VERSION 5.7 ;
  NOWIREEXTENSIONATPIN ON ;
  DIVIDERCHAR "/" ;
  BUSBITCHARS "[]" ;
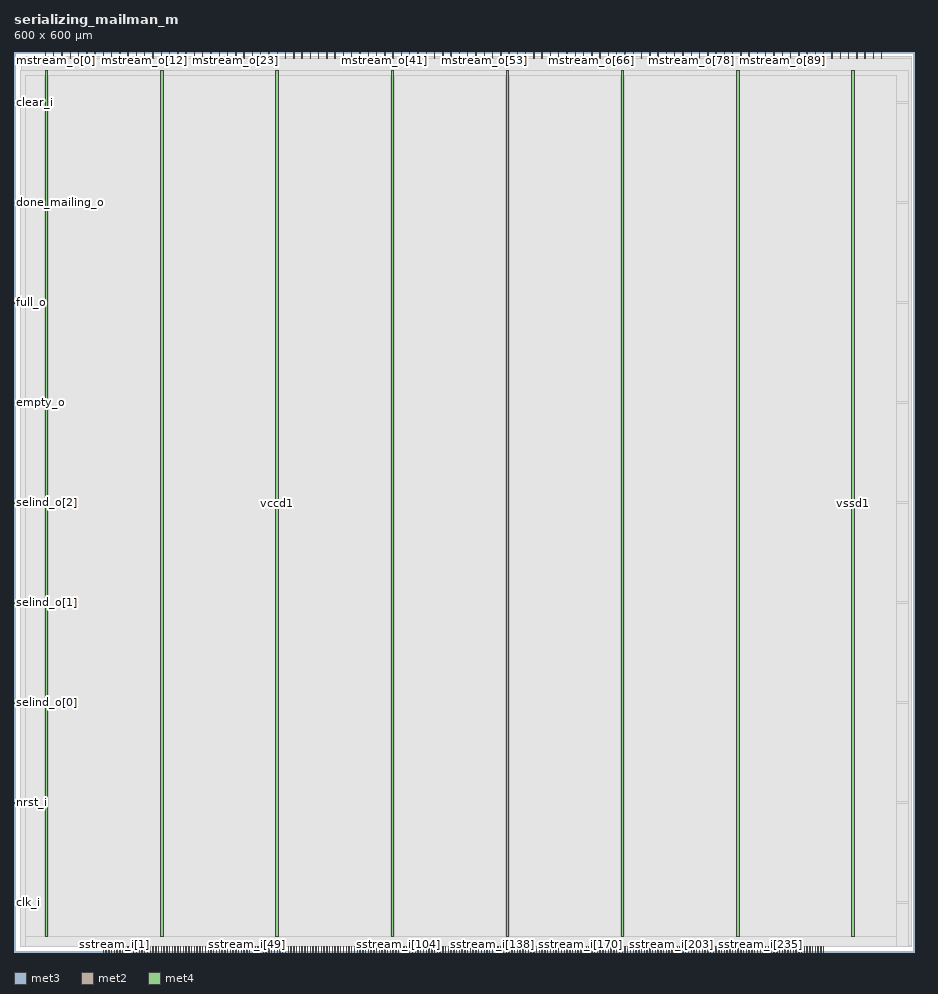
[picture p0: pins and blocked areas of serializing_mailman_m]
MACRO serializing_mailman_m
  CLASS BLOCK ;
  FOREIGN serializing_mailman_m ;
  ORIGIN 0.000 0.000 ;
  SIZE 600.000 BY 600.000 ;
  PIN clear_i
    DIRECTION INPUT ;
    USE SIGNAL ;
    ANTENNAGATEAREA 0.159000 ;
    PORT
      LAYER met3 ;
        RECT 0.000 565.800 4.000 566.400 ;
    END
  END clear_i
  PIN clk_i
    DIRECTION INPUT ;
    USE SIGNAL ;
    ANTENNAGATEAREA 0.852000 ;
    ANTENNADIFFAREA 0.434700 ;
    PORT
      LAYER met3 ;
        RECT 0.000 32.680 4.000 33.280 ;
    END
  END clk_i
  PIN done_mailing_o
    DIRECTION OUTPUT TRISTATE ;
    USE SIGNAL ;
    ANTENNADIFFAREA 0.795200 ;
    PORT
      LAYER met3 ;
        RECT 0.000 499.160 4.000 499.760 ;
    END
  END done_mailing_o
  PIN empty_o
    DIRECTION OUTPUT TRISTATE ;
    USE SIGNAL ;
    ANTENNADIFFAREA 0.795200 ;
    PORT
      LAYER met3 ;
        RECT 0.000 365.880 4.000 366.480 ;
    END
  END empty_o
  PIN full_o
    DIRECTION OUTPUT TRISTATE ;
    USE SIGNAL ;
    ANTENNADIFFAREA 0.795200 ;
    PORT
      LAYER met3 ;
        RECT 0.000 432.520 4.000 433.120 ;
    END
  END full_o
  PIN mstream_i[0]
    DIRECTION INPUT ;
    USE SIGNAL ;
    ANTENNAGATEAREA 0.213000 ;
    PORT
      LAYER met2 ;
        RECT 59.430 0.000 59.710 4.000 ;
    END
  END mstream_i[0]
  PIN mstream_i[1]
    DIRECTION INPUT ;
    USE SIGNAL ;
    ANTENNAGATEAREA 0.213000 ;
    PORT
      LAYER met2 ;
        RECT 61.270 0.000 61.550 4.000 ;
    END
  END mstream_i[1]
  PIN mstream_i[2]
    DIRECTION INPUT ;
    USE SIGNAL ;
    ANTENNAGATEAREA 0.213000 ;
    PORT
      LAYER met2 ;
        RECT 63.110 0.000 63.390 4.000 ;
    END
  END mstream_i[2]
  PIN mstream_o[0]
    DIRECTION OUTPUT TRISTATE ;
    USE SIGNAL ;
    ANTENNADIFFAREA 0.795200 ;
    PORT
      LAYER met2 ;
        RECT 20.790 596.000 21.070 600.000 ;
    END
  END mstream_o[0]
  PIN mstream_o[100]
    DIRECTION OUTPUT TRISTATE ;
    USE SIGNAL ;
    ANTENNADIFFAREA 0.795200 ;
    PORT
      LAYER met2 ;
        RECT 572.790 596.000 573.070 600.000 ;
    END
  END mstream_o[100]
  PIN mstream_o[101]
    DIRECTION OUTPUT TRISTATE ;
    USE SIGNAL ;
    PORT
      LAYER met2 ;
        RECT 578.310 596.000 578.590 600.000 ;
    END
  END mstream_o[101]
  PIN mstream_o[10]
    DIRECTION OUTPUT TRISTATE ;
    USE SIGNAL ;
    ANTENNADIFFAREA 0.795200 ;
    PORT
      LAYER met2 ;
        RECT 75.990 596.000 76.270 600.000 ;
    END
  END mstream_o[10]
  PIN mstream_o[11]
    DIRECTION OUTPUT TRISTATE ;
    USE SIGNAL ;
    ANTENNADIFFAREA 0.795200 ;
    PORT
      LAYER met2 ;
        RECT 81.510 596.000 81.790 600.000 ;
    END
  END mstream_o[11]
  PIN mstream_o[12]
    DIRECTION OUTPUT TRISTATE ;
    USE SIGNAL ;
    ANTENNADIFFAREA 0.795200 ;
    PORT
      LAYER met2 ;
        RECT 87.030 596.000 87.310 600.000 ;
    END
  END mstream_o[12]
  PIN mstream_o[13]
    DIRECTION OUTPUT TRISTATE ;
    USE SIGNAL ;
    ANTENNADIFFAREA 0.795200 ;
    PORT
      LAYER met2 ;
        RECT 92.550 596.000 92.830 600.000 ;
    END
  END mstream_o[13]
  PIN mstream_o[14]
    DIRECTION OUTPUT TRISTATE ;
    USE SIGNAL ;
    ANTENNADIFFAREA 0.795200 ;
    PORT
      LAYER met2 ;
        RECT 98.070 596.000 98.350 600.000 ;
    END
  END mstream_o[14]
  PIN mstream_o[15]
    DIRECTION OUTPUT TRISTATE ;
    USE SIGNAL ;
    ANTENNADIFFAREA 0.795200 ;
    PORT
      LAYER met2 ;
        RECT 103.590 596.000 103.870 600.000 ;
    END
  END mstream_o[15]
  PIN mstream_o[16]
    DIRECTION OUTPUT TRISTATE ;
    USE SIGNAL ;
    ANTENNADIFFAREA 0.795200 ;
    PORT
      LAYER met2 ;
        RECT 109.110 596.000 109.390 600.000 ;
    END
  END mstream_o[16]
  PIN mstream_o[17]
    DIRECTION OUTPUT TRISTATE ;
    USE SIGNAL ;
    ANTENNADIFFAREA 0.795200 ;
    PORT
      LAYER met2 ;
        RECT 114.630 596.000 114.910 600.000 ;
    END
  END mstream_o[17]
  PIN mstream_o[18]
    DIRECTION OUTPUT TRISTATE ;
    USE SIGNAL ;
    ANTENNADIFFAREA 0.795200 ;
    PORT
      LAYER met2 ;
        RECT 120.150 596.000 120.430 600.000 ;
    END
  END mstream_o[18]
  PIN mstream_o[19]
    DIRECTION OUTPUT TRISTATE ;
    USE SIGNAL ;
    ANTENNADIFFAREA 0.795200 ;
    PORT
      LAYER met2 ;
        RECT 125.670 596.000 125.950 600.000 ;
    END
  END mstream_o[19]
  PIN mstream_o[1]
    DIRECTION OUTPUT TRISTATE ;
    USE SIGNAL ;
    ANTENNADIFFAREA 0.795200 ;
    PORT
      LAYER met2 ;
        RECT 26.310 596.000 26.590 600.000 ;
    END
  END mstream_o[1]
  PIN mstream_o[20]
    DIRECTION OUTPUT TRISTATE ;
    USE SIGNAL ;
    ANTENNADIFFAREA 0.795200 ;
    PORT
      LAYER met2 ;
        RECT 131.190 596.000 131.470 600.000 ;
    END
  END mstream_o[20]
  PIN mstream_o[21]
    DIRECTION OUTPUT TRISTATE ;
    USE SIGNAL ;
    ANTENNADIFFAREA 0.795200 ;
    PORT
      LAYER met2 ;
        RECT 136.710 596.000 136.990 600.000 ;
    END
  END mstream_o[21]
  PIN mstream_o[22]
    DIRECTION OUTPUT TRISTATE ;
    USE SIGNAL ;
    ANTENNADIFFAREA 0.795200 ;
    PORT
      LAYER met2 ;
        RECT 142.230 596.000 142.510 600.000 ;
    END
  END mstream_o[22]
  PIN mstream_o[23]
    DIRECTION OUTPUT TRISTATE ;
    USE SIGNAL ;
    ANTENNADIFFAREA 0.795200 ;
    PORT
      LAYER met2 ;
        RECT 147.750 596.000 148.030 600.000 ;
    END
  END mstream_o[23]
  PIN mstream_o[24]
    DIRECTION OUTPUT TRISTATE ;
    USE SIGNAL ;
    ANTENNADIFFAREA 0.795200 ;
    PORT
      LAYER met2 ;
        RECT 153.270 596.000 153.550 600.000 ;
    END
  END mstream_o[24]
  PIN mstream_o[25]
    DIRECTION OUTPUT TRISTATE ;
    USE SIGNAL ;
    ANTENNADIFFAREA 0.795200 ;
    PORT
      LAYER met2 ;
        RECT 158.790 596.000 159.070 600.000 ;
    END
  END mstream_o[25]
  PIN mstream_o[26]
    DIRECTION OUTPUT TRISTATE ;
    USE SIGNAL ;
    ANTENNADIFFAREA 0.795200 ;
    PORT
      LAYER met2 ;
        RECT 164.310 596.000 164.590 600.000 ;
    END
  END mstream_o[26]
  PIN mstream_o[27]
    DIRECTION OUTPUT TRISTATE ;
    USE SIGNAL ;
    ANTENNADIFFAREA 0.795200 ;
    PORT
      LAYER met2 ;
        RECT 169.830 596.000 170.110 600.000 ;
    END
  END mstream_o[27]
  PIN mstream_o[28]
    DIRECTION OUTPUT TRISTATE ;
    USE SIGNAL ;
    ANTENNADIFFAREA 0.795200 ;
    PORT
      LAYER met2 ;
        RECT 175.350 596.000 175.630 600.000 ;
    END
  END mstream_o[28]
  PIN mstream_o[29]
    DIRECTION OUTPUT TRISTATE ;
    USE SIGNAL ;
    ANTENNADIFFAREA 0.795200 ;
    PORT
      LAYER met2 ;
        RECT 180.870 596.000 181.150 600.000 ;
    END
  END mstream_o[29]
  PIN mstream_o[2]
    DIRECTION OUTPUT TRISTATE ;
    USE SIGNAL ;
    ANTENNADIFFAREA 0.795200 ;
    PORT
      LAYER met2 ;
        RECT 31.830 596.000 32.110 600.000 ;
    END
  END mstream_o[2]
  PIN mstream_o[30]
    DIRECTION OUTPUT TRISTATE ;
    USE SIGNAL ;
    ANTENNADIFFAREA 0.795200 ;
    PORT
      LAYER met2 ;
        RECT 186.390 596.000 186.670 600.000 ;
    END
  END mstream_o[30]
  PIN mstream_o[31]
    DIRECTION OUTPUT TRISTATE ;
    USE SIGNAL ;
    ANTENNADIFFAREA 0.795200 ;
    PORT
      LAYER met2 ;
        RECT 191.910 596.000 192.190 600.000 ;
    END
  END mstream_o[31]
  PIN mstream_o[32]
    DIRECTION OUTPUT TRISTATE ;
    USE SIGNAL ;
    ANTENNADIFFAREA 0.795200 ;
    PORT
      LAYER met2 ;
        RECT 197.430 596.000 197.710 600.000 ;
    END
  END mstream_o[32]
  PIN mstream_o[33]
    DIRECTION OUTPUT TRISTATE ;
    USE SIGNAL ;
    PORT
      LAYER met2 ;
        RECT 202.950 596.000 203.230 600.000 ;
    END
  END mstream_o[33]
  PIN mstream_o[34]
    DIRECTION OUTPUT TRISTATE ;
    USE SIGNAL ;
    ANTENNADIFFAREA 0.795200 ;
    PORT
      LAYER met2 ;
        RECT 208.470 596.000 208.750 600.000 ;
    END
  END mstream_o[34]
  PIN mstream_o[35]
    DIRECTION OUTPUT TRISTATE ;
    USE SIGNAL ;
    ANTENNADIFFAREA 0.795200 ;
    PORT
      LAYER met2 ;
        RECT 213.990 596.000 214.270 600.000 ;
    END
  END mstream_o[35]
  PIN mstream_o[36]
    DIRECTION OUTPUT TRISTATE ;
    USE SIGNAL ;
    ANTENNADIFFAREA 0.795200 ;
    PORT
      LAYER met2 ;
        RECT 219.510 596.000 219.790 600.000 ;
    END
  END mstream_o[36]
  PIN mstream_o[37]
    DIRECTION OUTPUT TRISTATE ;
    USE SIGNAL ;
    ANTENNADIFFAREA 0.795200 ;
    PORT
      LAYER met2 ;
        RECT 225.030 596.000 225.310 600.000 ;
    END
  END mstream_o[37]
  PIN mstream_o[38]
    DIRECTION OUTPUT TRISTATE ;
    USE SIGNAL ;
    ANTENNADIFFAREA 0.795200 ;
    PORT
      LAYER met2 ;
        RECT 230.550 596.000 230.830 600.000 ;
    END
  END mstream_o[38]
  PIN mstream_o[39]
    DIRECTION OUTPUT TRISTATE ;
    USE SIGNAL ;
    ANTENNADIFFAREA 0.795200 ;
    PORT
      LAYER met2 ;
        RECT 236.070 596.000 236.350 600.000 ;
    END
  END mstream_o[39]
  PIN mstream_o[3]
    DIRECTION OUTPUT TRISTATE ;
    USE SIGNAL ;
    ANTENNADIFFAREA 0.795200 ;
    PORT
      LAYER met2 ;
        RECT 37.350 596.000 37.630 600.000 ;
    END
  END mstream_o[3]
  PIN mstream_o[40]
    DIRECTION OUTPUT TRISTATE ;
    USE SIGNAL ;
    ANTENNADIFFAREA 0.795200 ;
    PORT
      LAYER met2 ;
        RECT 241.590 596.000 241.870 600.000 ;
    END
  END mstream_o[40]
  PIN mstream_o[41]
    DIRECTION OUTPUT TRISTATE ;
    USE SIGNAL ;
    ANTENNADIFFAREA 0.795200 ;
    PORT
      LAYER met2 ;
        RECT 247.110 596.000 247.390 600.000 ;
    END
  END mstream_o[41]
  PIN mstream_o[42]
    DIRECTION OUTPUT TRISTATE ;
    USE SIGNAL ;
    ANTENNADIFFAREA 0.795200 ;
    PORT
      LAYER met2 ;
        RECT 252.630 596.000 252.910 600.000 ;
    END
  END mstream_o[42]
  PIN mstream_o[43]
    DIRECTION OUTPUT TRISTATE ;
    USE SIGNAL ;
    ANTENNADIFFAREA 0.795200 ;
    PORT
      LAYER met2 ;
        RECT 258.150 596.000 258.430 600.000 ;
    END
  END mstream_o[43]
  PIN mstream_o[44]
    DIRECTION OUTPUT TRISTATE ;
    USE SIGNAL ;
    ANTENNADIFFAREA 0.795200 ;
    PORT
      LAYER met2 ;
        RECT 263.670 596.000 263.950 600.000 ;
    END
  END mstream_o[44]
  PIN mstream_o[45]
    DIRECTION OUTPUT TRISTATE ;
    USE SIGNAL ;
    ANTENNADIFFAREA 0.795200 ;
    PORT
      LAYER met2 ;
        RECT 269.190 596.000 269.470 600.000 ;
    END
  END mstream_o[45]
  PIN mstream_o[46]
    DIRECTION OUTPUT TRISTATE ;
    USE SIGNAL ;
    ANTENNADIFFAREA 0.795200 ;
    PORT
      LAYER met2 ;
        RECT 274.710 596.000 274.990 600.000 ;
    END
  END mstream_o[46]
  PIN mstream_o[47]
    DIRECTION OUTPUT TRISTATE ;
    USE SIGNAL ;
    ANTENNADIFFAREA 0.795200 ;
    PORT
      LAYER met2 ;
        RECT 280.230 596.000 280.510 600.000 ;
    END
  END mstream_o[47]
  PIN mstream_o[48]
    DIRECTION OUTPUT TRISTATE ;
    USE SIGNAL ;
    ANTENNADIFFAREA 0.795200 ;
    PORT
      LAYER met2 ;
        RECT 285.750 596.000 286.030 600.000 ;
    END
  END mstream_o[48]
  PIN mstream_o[49]
    DIRECTION OUTPUT TRISTATE ;
    USE SIGNAL ;
    ANTENNADIFFAREA 0.795200 ;
    PORT
      LAYER met2 ;
        RECT 291.270 596.000 291.550 600.000 ;
    END
  END mstream_o[49]
  PIN mstream_o[4]
    DIRECTION OUTPUT TRISTATE ;
    USE SIGNAL ;
    ANTENNADIFFAREA 0.795200 ;
    PORT
      LAYER met2 ;
        RECT 42.870 596.000 43.150 600.000 ;
    END
  END mstream_o[4]
  PIN mstream_o[50]
    DIRECTION OUTPUT TRISTATE ;
    USE SIGNAL ;
    ANTENNADIFFAREA 0.795200 ;
    PORT
      LAYER met2 ;
        RECT 296.790 596.000 297.070 600.000 ;
    END
  END mstream_o[50]
  PIN mstream_o[51]
    DIRECTION OUTPUT TRISTATE ;
    USE SIGNAL ;
    ANTENNADIFFAREA 0.795200 ;
    PORT
      LAYER met2 ;
        RECT 302.310 596.000 302.590 600.000 ;
    END
  END mstream_o[51]
  PIN mstream_o[52]
    DIRECTION OUTPUT TRISTATE ;
    USE SIGNAL ;
    ANTENNADIFFAREA 0.795200 ;
    PORT
      LAYER met2 ;
        RECT 307.830 596.000 308.110 600.000 ;
    END
  END mstream_o[52]
  PIN mstream_o[53]
    DIRECTION OUTPUT TRISTATE ;
    USE SIGNAL ;
    ANTENNADIFFAREA 0.795200 ;
    PORT
      LAYER met2 ;
        RECT 313.350 596.000 313.630 600.000 ;
    END
  END mstream_o[53]
  PIN mstream_o[54]
    DIRECTION OUTPUT TRISTATE ;
    USE SIGNAL ;
    ANTENNADIFFAREA 0.795200 ;
    PORT
      LAYER met2 ;
        RECT 318.870 596.000 319.150 600.000 ;
    END
  END mstream_o[54]
  PIN mstream_o[55]
    DIRECTION OUTPUT TRISTATE ;
    USE SIGNAL ;
    ANTENNADIFFAREA 0.795200 ;
    PORT
      LAYER met2 ;
        RECT 324.390 596.000 324.670 600.000 ;
    END
  END mstream_o[55]
  PIN mstream_o[56]
    DIRECTION OUTPUT TRISTATE ;
    USE SIGNAL ;
    ANTENNADIFFAREA 0.795200 ;
    PORT
      LAYER met2 ;
        RECT 329.910 596.000 330.190 600.000 ;
    END
  END mstream_o[56]
  PIN mstream_o[57]
    DIRECTION OUTPUT TRISTATE ;
    USE SIGNAL ;
    ANTENNADIFFAREA 0.795200 ;
    PORT
      LAYER met2 ;
        RECT 335.430 596.000 335.710 600.000 ;
    END
  END mstream_o[57]
  PIN mstream_o[58]
    DIRECTION OUTPUT TRISTATE ;
    USE SIGNAL ;
    ANTENNADIFFAREA 0.795200 ;
    PORT
      LAYER met2 ;
        RECT 340.950 596.000 341.230 600.000 ;
    END
  END mstream_o[58]
  PIN mstream_o[59]
    DIRECTION OUTPUT TRISTATE ;
    USE SIGNAL ;
    ANTENNADIFFAREA 0.795200 ;
    PORT
      LAYER met2 ;
        RECT 346.470 596.000 346.750 600.000 ;
    END
  END mstream_o[59]
  PIN mstream_o[5]
    DIRECTION OUTPUT TRISTATE ;
    USE SIGNAL ;
    ANTENNADIFFAREA 0.795200 ;
    PORT
      LAYER met2 ;
        RECT 48.390 596.000 48.670 600.000 ;
    END
  END mstream_o[5]
  PIN mstream_o[60]
    DIRECTION OUTPUT TRISTATE ;
    USE SIGNAL ;
    ANTENNADIFFAREA 0.795200 ;
    PORT
      LAYER met2 ;
        RECT 351.990 596.000 352.270 600.000 ;
    END
  END mstream_o[60]
  PIN mstream_o[61]
    DIRECTION OUTPUT TRISTATE ;
    USE SIGNAL ;
    ANTENNADIFFAREA 0.795200 ;
    PORT
      LAYER met2 ;
        RECT 357.510 596.000 357.790 600.000 ;
    END
  END mstream_o[61]
  PIN mstream_o[62]
    DIRECTION OUTPUT TRISTATE ;
    USE SIGNAL ;
    ANTENNADIFFAREA 0.795200 ;
    PORT
      LAYER met2 ;
        RECT 363.030 596.000 363.310 600.000 ;
    END
  END mstream_o[62]
  PIN mstream_o[63]
    DIRECTION OUTPUT TRISTATE ;
    USE SIGNAL ;
    ANTENNADIFFAREA 0.795200 ;
    PORT
      LAYER met2 ;
        RECT 368.550 596.000 368.830 600.000 ;
    END
  END mstream_o[63]
  PIN mstream_o[64]
    DIRECTION OUTPUT TRISTATE ;
    USE SIGNAL ;
    ANTENNADIFFAREA 0.795200 ;
    PORT
      LAYER met2 ;
        RECT 374.070 596.000 374.350 600.000 ;
    END
  END mstream_o[64]
  PIN mstream_o[65]
    DIRECTION OUTPUT TRISTATE ;
    USE SIGNAL ;
    ANTENNADIFFAREA 0.795200 ;
    PORT
      LAYER met2 ;
        RECT 379.590 596.000 379.870 600.000 ;
    END
  END mstream_o[65]
  PIN mstream_o[66]
    DIRECTION OUTPUT TRISTATE ;
    USE SIGNAL ;
    ANTENNADIFFAREA 0.795200 ;
    PORT
      LAYER met2 ;
        RECT 385.110 596.000 385.390 600.000 ;
    END
  END mstream_o[66]
  PIN mstream_o[67]
    DIRECTION OUTPUT TRISTATE ;
    USE SIGNAL ;
    PORT
      LAYER met2 ;
        RECT 390.630 596.000 390.910 600.000 ;
    END
  END mstream_o[67]
  PIN mstream_o[68]
    DIRECTION OUTPUT TRISTATE ;
    USE SIGNAL ;
    ANTENNADIFFAREA 0.795200 ;
    PORT
      LAYER met2 ;
        RECT 396.150 596.000 396.430 600.000 ;
    END
  END mstream_o[68]
  PIN mstream_o[69]
    DIRECTION OUTPUT TRISTATE ;
    USE SIGNAL ;
    ANTENNADIFFAREA 0.795200 ;
    PORT
      LAYER met2 ;
        RECT 401.670 596.000 401.950 600.000 ;
    END
  END mstream_o[69]
  PIN mstream_o[6]
    DIRECTION OUTPUT TRISTATE ;
    USE SIGNAL ;
    ANTENNADIFFAREA 0.795200 ;
    PORT
      LAYER met2 ;
        RECT 53.910 596.000 54.190 600.000 ;
    END
  END mstream_o[6]
  PIN mstream_o[70]
    DIRECTION OUTPUT TRISTATE ;
    USE SIGNAL ;
    ANTENNADIFFAREA 0.795200 ;
    PORT
      LAYER met2 ;
        RECT 407.190 596.000 407.470 600.000 ;
    END
  END mstream_o[70]
  PIN mstream_o[71]
    DIRECTION OUTPUT TRISTATE ;
    USE SIGNAL ;
    ANTENNADIFFAREA 0.795200 ;
    PORT
      LAYER met2 ;
        RECT 412.710 596.000 412.990 600.000 ;
    END
  END mstream_o[71]
  PIN mstream_o[72]
    DIRECTION OUTPUT TRISTATE ;
    USE SIGNAL ;
    ANTENNADIFFAREA 0.795200 ;
    PORT
      LAYER met2 ;
        RECT 418.230 596.000 418.510 600.000 ;
    END
  END mstream_o[72]
  PIN mstream_o[73]
    DIRECTION OUTPUT TRISTATE ;
    USE SIGNAL ;
    ANTENNADIFFAREA 0.795200 ;
    PORT
      LAYER met2 ;
        RECT 423.750 596.000 424.030 600.000 ;
    END
  END mstream_o[73]
  PIN mstream_o[74]
    DIRECTION OUTPUT TRISTATE ;
    USE SIGNAL ;
    ANTENNADIFFAREA 0.795200 ;
    PORT
      LAYER met2 ;
        RECT 429.270 596.000 429.550 600.000 ;
    END
  END mstream_o[74]
  PIN mstream_o[75]
    DIRECTION OUTPUT TRISTATE ;
    USE SIGNAL ;
    ANTENNADIFFAREA 0.795200 ;
    PORT
      LAYER met2 ;
        RECT 434.790 596.000 435.070 600.000 ;
    END
  END mstream_o[75]
  PIN mstream_o[76]
    DIRECTION OUTPUT TRISTATE ;
    USE SIGNAL ;
    ANTENNADIFFAREA 0.795200 ;
    PORT
      LAYER met2 ;
        RECT 440.310 596.000 440.590 600.000 ;
    END
  END mstream_o[76]
  PIN mstream_o[77]
    DIRECTION OUTPUT TRISTATE ;
    USE SIGNAL ;
    ANTENNADIFFAREA 0.795200 ;
    PORT
      LAYER met2 ;
        RECT 445.830 596.000 446.110 600.000 ;
    END
  END mstream_o[77]
  PIN mstream_o[78]
    DIRECTION OUTPUT TRISTATE ;
    USE SIGNAL ;
    ANTENNADIFFAREA 0.795200 ;
    PORT
      LAYER met2 ;
        RECT 451.350 596.000 451.630 600.000 ;
    END
  END mstream_o[78]
  PIN mstream_o[79]
    DIRECTION OUTPUT TRISTATE ;
    USE SIGNAL ;
    ANTENNADIFFAREA 0.795200 ;
    PORT
      LAYER met2 ;
        RECT 456.870 596.000 457.150 600.000 ;
    END
  END mstream_o[79]
  PIN mstream_o[7]
    DIRECTION OUTPUT TRISTATE ;
    USE SIGNAL ;
    ANTENNADIFFAREA 0.795200 ;
    PORT
      LAYER met2 ;
        RECT 59.430 596.000 59.710 600.000 ;
    END
  END mstream_o[7]
  PIN mstream_o[80]
    DIRECTION OUTPUT TRISTATE ;
    USE SIGNAL ;
    ANTENNADIFFAREA 0.795200 ;
    PORT
      LAYER met2 ;
        RECT 462.390 596.000 462.670 600.000 ;
    END
  END mstream_o[80]
  PIN mstream_o[81]
    DIRECTION OUTPUT TRISTATE ;
    USE SIGNAL ;
    ANTENNADIFFAREA 0.795200 ;
    PORT
      LAYER met2 ;
        RECT 467.910 596.000 468.190 600.000 ;
    END
  END mstream_o[81]
  PIN mstream_o[82]
    DIRECTION OUTPUT TRISTATE ;
    USE SIGNAL ;
    ANTENNADIFFAREA 0.795200 ;
    PORT
      LAYER met2 ;
        RECT 473.430 596.000 473.710 600.000 ;
    END
  END mstream_o[82]
  PIN mstream_o[83]
    DIRECTION OUTPUT TRISTATE ;
    USE SIGNAL ;
    ANTENNADIFFAREA 0.795200 ;
    PORT
      LAYER met2 ;
        RECT 478.950 596.000 479.230 600.000 ;
    END
  END mstream_o[83]
  PIN mstream_o[84]
    DIRECTION OUTPUT TRISTATE ;
    USE SIGNAL ;
    ANTENNADIFFAREA 0.795200 ;
    PORT
      LAYER met2 ;
        RECT 484.470 596.000 484.750 600.000 ;
    END
  END mstream_o[84]
  PIN mstream_o[85]
    DIRECTION OUTPUT TRISTATE ;
    USE SIGNAL ;
    ANTENNADIFFAREA 0.795200 ;
    PORT
      LAYER met2 ;
        RECT 489.990 596.000 490.270 600.000 ;
    END
  END mstream_o[85]
  PIN mstream_o[86]
    DIRECTION OUTPUT TRISTATE ;
    USE SIGNAL ;
    ANTENNADIFFAREA 0.795200 ;
    PORT
      LAYER met2 ;
        RECT 495.510 596.000 495.790 600.000 ;
    END
  END mstream_o[86]
  PIN mstream_o[87]
    DIRECTION OUTPUT TRISTATE ;
    USE SIGNAL ;
    ANTENNADIFFAREA 0.795200 ;
    PORT
      LAYER met2 ;
        RECT 501.030 596.000 501.310 600.000 ;
    END
  END mstream_o[87]
  PIN mstream_o[88]
    DIRECTION OUTPUT TRISTATE ;
    USE SIGNAL ;
    ANTENNADIFFAREA 0.795200 ;
    PORT
      LAYER met2 ;
        RECT 506.550 596.000 506.830 600.000 ;
    END
  END mstream_o[88]
  PIN mstream_o[89]
    DIRECTION OUTPUT TRISTATE ;
    USE SIGNAL ;
    ANTENNADIFFAREA 0.795200 ;
    PORT
      LAYER met2 ;
        RECT 512.070 596.000 512.350 600.000 ;
    END
  END mstream_o[89]
  PIN mstream_o[8]
    DIRECTION OUTPUT TRISTATE ;
    USE SIGNAL ;
    ANTENNADIFFAREA 0.795200 ;
    PORT
      LAYER met2 ;
        RECT 64.950 596.000 65.230 600.000 ;
    END
  END mstream_o[8]
  PIN mstream_o[90]
    DIRECTION OUTPUT TRISTATE ;
    USE SIGNAL ;
    ANTENNADIFFAREA 0.795200 ;
    PORT
      LAYER met2 ;
        RECT 517.590 596.000 517.870 600.000 ;
    END
  END mstream_o[90]
  PIN mstream_o[91]
    DIRECTION OUTPUT TRISTATE ;
    USE SIGNAL ;
    ANTENNADIFFAREA 0.795200 ;
    PORT
      LAYER met2 ;
        RECT 523.110 596.000 523.390 600.000 ;
    END
  END mstream_o[91]
  PIN mstream_o[92]
    DIRECTION OUTPUT TRISTATE ;
    USE SIGNAL ;
    ANTENNADIFFAREA 0.795200 ;
    PORT
      LAYER met2 ;
        RECT 528.630 596.000 528.910 600.000 ;
    END
  END mstream_o[92]
  PIN mstream_o[93]
    DIRECTION OUTPUT TRISTATE ;
    USE SIGNAL ;
    ANTENNADIFFAREA 0.795200 ;
    PORT
      LAYER met2 ;
        RECT 534.150 596.000 534.430 600.000 ;
    END
  END mstream_o[93]
  PIN mstream_o[94]
    DIRECTION OUTPUT TRISTATE ;
    USE SIGNAL ;
    ANTENNADIFFAREA 0.795200 ;
    PORT
      LAYER met2 ;
        RECT 539.670 596.000 539.950 600.000 ;
    END
  END mstream_o[94]
  PIN mstream_o[95]
    DIRECTION OUTPUT TRISTATE ;
    USE SIGNAL ;
    ANTENNADIFFAREA 0.795200 ;
    PORT
      LAYER met2 ;
        RECT 545.190 596.000 545.470 600.000 ;
    END
  END mstream_o[95]
  PIN mstream_o[96]
    DIRECTION OUTPUT TRISTATE ;
    USE SIGNAL ;
    ANTENNADIFFAREA 0.795200 ;
    PORT
      LAYER met2 ;
        RECT 550.710 596.000 550.990 600.000 ;
    END
  END mstream_o[96]
  PIN mstream_o[97]
    DIRECTION OUTPUT TRISTATE ;
    USE SIGNAL ;
    ANTENNADIFFAREA 0.795200 ;
    PORT
      LAYER met2 ;
        RECT 556.230 596.000 556.510 600.000 ;
    END
  END mstream_o[97]
  PIN mstream_o[98]
    DIRECTION OUTPUT TRISTATE ;
    USE SIGNAL ;
    ANTENNADIFFAREA 0.795200 ;
    PORT
      LAYER met2 ;
        RECT 561.750 596.000 562.030 600.000 ;
    END
  END mstream_o[98]
  PIN mstream_o[99]
    DIRECTION OUTPUT TRISTATE ;
    USE SIGNAL ;
    ANTENNADIFFAREA 0.795200 ;
    PORT
      LAYER met2 ;
        RECT 567.270 596.000 567.550 600.000 ;
    END
  END mstream_o[99]
  PIN mstream_o[9]
    DIRECTION OUTPUT TRISTATE ;
    USE SIGNAL ;
    ANTENNADIFFAREA 0.795200 ;
    PORT
      LAYER met2 ;
        RECT 70.470 596.000 70.750 600.000 ;
    END
  END mstream_o[9]
  PIN nrst_i
    DIRECTION INPUT ;
    USE SIGNAL ;
    ANTENNAGATEAREA 0.196500 ;
    PORT
      LAYER met3 ;
        RECT 0.000 99.320 4.000 99.920 ;
    END
  END nrst_i
  PIN selind_o[0]
    DIRECTION OUTPUT TRISTATE ;
    USE SIGNAL ;
    ANTENNADIFFAREA 0.795200 ;
    PORT
      LAYER met3 ;
        RECT 0.000 165.960 4.000 166.560 ;
    END
  END selind_o[0]
  PIN selind_o[1]
    DIRECTION OUTPUT TRISTATE ;
    USE SIGNAL ;
    ANTENNADIFFAREA 0.795200 ;
    PORT
      LAYER met3 ;
        RECT 0.000 232.600 4.000 233.200 ;
    END
  END selind_o[1]
  PIN selind_o[2]
    DIRECTION OUTPUT TRISTATE ;
    USE SIGNAL ;
    ANTENNADIFFAREA 0.795200 ;
    PORT
      LAYER met3 ;
        RECT 0.000 299.240 4.000 299.840 ;
    END
  END selind_o[2]
  PIN sstream_i[0]
    DIRECTION INPUT ;
    USE SIGNAL ;
    ANTENNAGATEAREA 0.196500 ;
    PORT
      LAYER met2 ;
        RECT 64.950 0.000 65.230 4.000 ;
    END
  END sstream_i[0]
  PIN sstream_i[100]
    DIRECTION INPUT ;
    USE SIGNAL ;
    ANTENNAGATEAREA 0.159000 ;
    PORT
      LAYER met2 ;
        RECT 248.950 0.000 249.230 4.000 ;
    END
  END sstream_i[100]
  PIN sstream_i[101]
    DIRECTION INPUT ;
    USE SIGNAL ;
    ANTENNAGATEAREA 0.159000 ;
    PORT
      LAYER met2 ;
        RECT 250.790 0.000 251.070 4.000 ;
    END
  END sstream_i[101]
  PIN sstream_i[102]
    DIRECTION INPUT ;
    USE SIGNAL ;
    ANTENNAGATEAREA 0.159000 ;
    PORT
      LAYER met2 ;
        RECT 252.630 0.000 252.910 4.000 ;
    END
  END sstream_i[102]
  PIN sstream_i[103]
    DIRECTION INPUT ;
    USE SIGNAL ;
    ANTENNAGATEAREA 0.213000 ;
    PORT
      LAYER met2 ;
        RECT 254.470 0.000 254.750 4.000 ;
    END
  END sstream_i[103]
  PIN sstream_i[104]
    DIRECTION INPUT ;
    USE SIGNAL ;
    ANTENNAGATEAREA 0.159000 ;
    PORT
      LAYER met2 ;
        RECT 256.310 0.000 256.590 4.000 ;
    END
  END sstream_i[104]
  PIN sstream_i[105]
    DIRECTION INPUT ;
    USE SIGNAL ;
    ANTENNAGATEAREA 0.159000 ;
    PORT
      LAYER met2 ;
        RECT 258.150 0.000 258.430 4.000 ;
    END
  END sstream_i[105]
  PIN sstream_i[106]
    DIRECTION INPUT ;
    USE SIGNAL ;
    ANTENNAGATEAREA 0.213000 ;
    PORT
      LAYER met2 ;
        RECT 259.990 0.000 260.270 4.000 ;
    END
  END sstream_i[106]
  PIN sstream_i[107]
    DIRECTION INPUT ;
    USE SIGNAL ;
    ANTENNAGATEAREA 0.159000 ;
    PORT
      LAYER met2 ;
        RECT 261.830 0.000 262.110 4.000 ;
    END
  END sstream_i[107]
  PIN sstream_i[108]
    DIRECTION INPUT ;
    USE SIGNAL ;
    ANTENNAGATEAREA 0.247500 ;
    PORT
      LAYER met2 ;
        RECT 263.670 0.000 263.950 4.000 ;
    END
  END sstream_i[108]
  PIN sstream_i[109]
    DIRECTION INPUT ;
    USE SIGNAL ;
    ANTENNAGATEAREA 0.213000 ;
    PORT
      LAYER met2 ;
        RECT 265.510 0.000 265.790 4.000 ;
    END
  END sstream_i[109]
  PIN sstream_i[10]
    DIRECTION INPUT ;
    USE SIGNAL ;
    ANTENNAGATEAREA 0.159000 ;
    PORT
      LAYER met2 ;
        RECT 83.350 0.000 83.630 4.000 ;
    END
  END sstream_i[10]
  PIN sstream_i[110]
    DIRECTION INPUT ;
    USE SIGNAL ;
    ANTENNAGATEAREA 0.213000 ;
    PORT
      LAYER met2 ;
        RECT 267.350 0.000 267.630 4.000 ;
    END
  END sstream_i[110]
  PIN sstream_i[111]
    DIRECTION INPUT ;
    USE SIGNAL ;
    ANTENNAGATEAREA 0.247500 ;
    PORT
      LAYER met2 ;
        RECT 269.190 0.000 269.470 4.000 ;
    END
  END sstream_i[111]
  PIN sstream_i[112]
    DIRECTION INPUT ;
    USE SIGNAL ;
    ANTENNAGATEAREA 0.247500 ;
    PORT
      LAYER met2 ;
        RECT 271.030 0.000 271.310 4.000 ;
    END
  END sstream_i[112]
  PIN sstream_i[113]
    DIRECTION INPUT ;
    USE SIGNAL ;
    ANTENNAGATEAREA 0.247500 ;
    PORT
      LAYER met2 ;
        RECT 272.870 0.000 273.150 4.000 ;
    END
  END sstream_i[113]
  PIN sstream_i[114]
    DIRECTION INPUT ;
    USE SIGNAL ;
    ANTENNAGATEAREA 0.247500 ;
    PORT
      LAYER met2 ;
        RECT 274.710 0.000 274.990 4.000 ;
    END
  END sstream_i[114]
  PIN sstream_i[115]
    DIRECTION INPUT ;
    USE SIGNAL ;
    ANTENNAGATEAREA 0.159000 ;
    PORT
      LAYER met2 ;
        RECT 276.550 0.000 276.830 4.000 ;
    END
  END sstream_i[115]
  PIN sstream_i[116]
    DIRECTION INPUT ;
    USE SIGNAL ;
    ANTENNAGATEAREA 0.247500 ;
    PORT
      LAYER met2 ;
        RECT 278.390 0.000 278.670 4.000 ;
    END
  END sstream_i[116]
  PIN sstream_i[117]
    DIRECTION INPUT ;
    USE SIGNAL ;
    ANTENNAGATEAREA 0.213000 ;
    PORT
      LAYER met2 ;
        RECT 280.230 0.000 280.510 4.000 ;
    END
  END sstream_i[117]
  PIN sstream_i[118]
    DIRECTION INPUT ;
    USE SIGNAL ;
    ANTENNAGATEAREA 0.159000 ;
    PORT
      LAYER met2 ;
        RECT 282.070 0.000 282.350 4.000 ;
    END
  END sstream_i[118]
  PIN sstream_i[119]
    DIRECTION INPUT ;
    USE SIGNAL ;
    ANTENNAGATEAREA 0.213000 ;
    PORT
      LAYER met2 ;
        RECT 283.910 0.000 284.190 4.000 ;
    END
  END sstream_i[119]
  PIN sstream_i[11]
    DIRECTION INPUT ;
    USE SIGNAL ;
    ANTENNAGATEAREA 0.213000 ;
    PORT
      LAYER met2 ;
        RECT 85.190 0.000 85.470 4.000 ;
    END
  END sstream_i[11]
  PIN sstream_i[120]
    DIRECTION INPUT ;
    USE SIGNAL ;
    ANTENNAGATEAREA 0.159000 ;
    PORT
      LAYER met2 ;
        RECT 285.750 0.000 286.030 4.000 ;
    END
  END sstream_i[120]
  PIN sstream_i[121]
    DIRECTION INPUT ;
    USE SIGNAL ;
    ANTENNAGATEAREA 0.213000 ;
    PORT
      LAYER met2 ;
        RECT 287.590 0.000 287.870 4.000 ;
    END
  END sstream_i[121]
  PIN sstream_i[122]
    DIRECTION INPUT ;
    USE SIGNAL ;
    ANTENNAGATEAREA 0.159000 ;
    PORT
      LAYER met2 ;
        RECT 289.430 0.000 289.710 4.000 ;
    END
  END sstream_i[122]
  PIN sstream_i[123]
    DIRECTION INPUT ;
    USE SIGNAL ;
    ANTENNAGATEAREA 0.213000 ;
    PORT
      LAYER met2 ;
        RECT 291.270 0.000 291.550 4.000 ;
    END
  END sstream_i[123]
  PIN sstream_i[124]
    DIRECTION INPUT ;
    USE SIGNAL ;
    ANTENNAGATEAREA 0.196500 ;
    PORT
      LAYER met2 ;
        RECT 293.110 0.000 293.390 4.000 ;
    END
  END sstream_i[124]
  PIN sstream_i[125]
    DIRECTION INPUT ;
    USE SIGNAL ;
    ANTENNAGATEAREA 0.196500 ;
    PORT
      LAYER met2 ;
        RECT 294.950 0.000 295.230 4.000 ;
    END
  END sstream_i[125]
  PIN sstream_i[126]
    DIRECTION INPUT ;
    USE SIGNAL ;
    ANTENNAGATEAREA 0.196500 ;
    PORT
      LAYER met2 ;
        RECT 296.790 0.000 297.070 4.000 ;
    END
  END sstream_i[126]
  PIN sstream_i[127]
    DIRECTION INPUT ;
    USE SIGNAL ;
    ANTENNAGATEAREA 0.196500 ;
    PORT
      LAYER met2 ;
        RECT 298.630 0.000 298.910 4.000 ;
    END
  END sstream_i[127]
  PIN sstream_i[128]
    DIRECTION INPUT ;
    USE SIGNAL ;
    ANTENNAGATEAREA 0.126000 ;
    PORT
      LAYER met2 ;
        RECT 300.470 0.000 300.750 4.000 ;
    END
  END sstream_i[128]
  PIN sstream_i[129]
    DIRECTION INPUT ;
    USE SIGNAL ;
    ANTENNAGATEAREA 0.196500 ;
    PORT
      LAYER met2 ;
        RECT 302.310 0.000 302.590 4.000 ;
    END
  END sstream_i[129]
  PIN sstream_i[12]
    DIRECTION INPUT ;
    USE SIGNAL ;
    ANTENNAGATEAREA 0.213000 ;
    PORT
      LAYER met2 ;
        RECT 87.030 0.000 87.310 4.000 ;
    END
  END sstream_i[12]
  PIN sstream_i[130]
    DIRECTION INPUT ;
    USE SIGNAL ;
    ANTENNAGATEAREA 0.159000 ;
    PORT
      LAYER met2 ;
        RECT 304.150 0.000 304.430 4.000 ;
    END
  END sstream_i[130]
  PIN sstream_i[131]
    DIRECTION INPUT ;
    USE SIGNAL ;
    ANTENNAGATEAREA 0.159000 ;
    PORT
      LAYER met2 ;
        RECT 305.990 0.000 306.270 4.000 ;
    END
  END sstream_i[131]
  PIN sstream_i[132]
    DIRECTION INPUT ;
    USE SIGNAL ;
    ANTENNAGATEAREA 0.159000 ;
    PORT
      LAYER met2 ;
        RECT 307.830 0.000 308.110 4.000 ;
    END
  END sstream_i[132]
  PIN sstream_i[133]
    DIRECTION INPUT ;
    USE SIGNAL ;
    ANTENNAGATEAREA 0.159000 ;
    PORT
      LAYER met2 ;
        RECT 309.670 0.000 309.950 4.000 ;
    END
  END sstream_i[133]
  PIN sstream_i[134]
    DIRECTION INPUT ;
    USE SIGNAL ;
    ANTENNAGATEAREA 0.213000 ;
    PORT
      LAYER met2 ;
        RECT 311.510 0.000 311.790 4.000 ;
    END
  END sstream_i[134]
  PIN sstream_i[135]
    DIRECTION INPUT ;
    USE SIGNAL ;
    ANTENNAGATEAREA 0.159000 ;
    PORT
      LAYER met2 ;
        RECT 313.350 0.000 313.630 4.000 ;
    END
  END sstream_i[135]
  PIN sstream_i[136]
    DIRECTION INPUT ;
    USE SIGNAL ;
    ANTENNAGATEAREA 0.159000 ;
    PORT
      LAYER met2 ;
        RECT 315.190 0.000 315.470 4.000 ;
    END
  END sstream_i[136]
  PIN sstream_i[137]
    DIRECTION INPUT ;
    USE SIGNAL ;
    ANTENNAGATEAREA 0.159000 ;
    PORT
      LAYER met2 ;
        RECT 317.030 0.000 317.310 4.000 ;
    END
  END sstream_i[137]
  PIN sstream_i[138]
    DIRECTION INPUT ;
    USE SIGNAL ;
    ANTENNAGATEAREA 0.213000 ;
    PORT
      LAYER met2 ;
        RECT 318.870 0.000 319.150 4.000 ;
    END
  END sstream_i[138]
  PIN sstream_i[139]
    DIRECTION INPUT ;
    USE SIGNAL ;
    ANTENNAGATEAREA 0.213000 ;
    PORT
      LAYER met2 ;
        RECT 320.710 0.000 320.990 4.000 ;
    END
  END sstream_i[139]
  PIN sstream_i[13]
    DIRECTION INPUT ;
    USE SIGNAL ;
    ANTENNAGATEAREA 0.213000 ;
    PORT
      LAYER met2 ;
        RECT 88.870 0.000 89.150 4.000 ;
    END
  END sstream_i[13]
  PIN sstream_i[140]
    DIRECTION INPUT ;
    USE SIGNAL ;
    ANTENNAGATEAREA 0.213000 ;
    PORT
      LAYER met2 ;
        RECT 322.550 0.000 322.830 4.000 ;
    END
  END sstream_i[140]
  PIN sstream_i[141]
    DIRECTION INPUT ;
    USE SIGNAL ;
    ANTENNAGATEAREA 0.247500 ;
    PORT
      LAYER met2 ;
        RECT 324.390 0.000 324.670 4.000 ;
    END
  END sstream_i[141]
  PIN sstream_i[142]
    DIRECTION INPUT ;
    USE SIGNAL ;
    ANTENNAGATEAREA 0.247500 ;
    ANTENNADIFFAREA 0.434700 ;
    PORT
      LAYER met2 ;
        RECT 326.230 0.000 326.510 4.000 ;
    END
  END sstream_i[142]
  PIN sstream_i[143]
    DIRECTION INPUT ;
    USE SIGNAL ;
    ANTENNAGATEAREA 0.247500 ;
    PORT
      LAYER met2 ;
        RECT 328.070 0.000 328.350 4.000 ;
    END
  END sstream_i[143]
  PIN sstream_i[144]
    DIRECTION INPUT ;
    USE SIGNAL ;
    ANTENNAGATEAREA 0.247500 ;
    PORT
      LAYER met2 ;
        RECT 329.910 0.000 330.190 4.000 ;
    END
  END sstream_i[144]
  PIN sstream_i[145]
    DIRECTION INPUT ;
    USE SIGNAL ;
    ANTENNAGATEAREA 0.247500 ;
    PORT
      LAYER met2 ;
        RECT 331.750 0.000 332.030 4.000 ;
    END
  END sstream_i[145]
  PIN sstream_i[146]
    DIRECTION INPUT ;
    USE SIGNAL ;
    ANTENNAGATEAREA 0.247500 ;
    PORT
      LAYER met2 ;
        RECT 333.590 0.000 333.870 4.000 ;
    END
  END sstream_i[146]
  PIN sstream_i[147]
    DIRECTION INPUT ;
    USE SIGNAL ;
    ANTENNAGATEAREA 0.213000 ;
    PORT
      LAYER met2 ;
        RECT 335.430 0.000 335.710 4.000 ;
    END
  END sstream_i[147]
  PIN sstream_i[148]
    DIRECTION INPUT ;
    USE SIGNAL ;
    ANTENNAGATEAREA 0.247500 ;
    PORT
      LAYER met2 ;
        RECT 337.270 0.000 337.550 4.000 ;
    END
  END sstream_i[148]
  PIN sstream_i[149]
    DIRECTION INPUT ;
    USE SIGNAL ;
    ANTENNAGATEAREA 0.247500 ;
    PORT
      LAYER met2 ;
        RECT 339.110 0.000 339.390 4.000 ;
    END
  END sstream_i[149]
  PIN sstream_i[14]
    DIRECTION INPUT ;
    USE SIGNAL ;
    ANTENNAGATEAREA 0.213000 ;
    PORT
      LAYER met2 ;
        RECT 90.710 0.000 90.990 4.000 ;
    END
  END sstream_i[14]
  PIN sstream_i[150]
    DIRECTION INPUT ;
    USE SIGNAL ;
    ANTENNAGATEAREA 0.159000 ;
    PORT
      LAYER met2 ;
        RECT 340.950 0.000 341.230 4.000 ;
    END
  END sstream_i[150]
  PIN sstream_i[151]
    DIRECTION INPUT ;
    USE SIGNAL ;
    ANTENNAGATEAREA 0.196500 ;
    PORT
      LAYER met2 ;
        RECT 342.790 0.000 343.070 4.000 ;
    END
  END sstream_i[151]
  PIN sstream_i[152]
    DIRECTION INPUT ;
    USE SIGNAL ;
    ANTENNAGATEAREA 0.196500 ;
    PORT
      LAYER met2 ;
        RECT 344.630 0.000 344.910 4.000 ;
    END
  END sstream_i[152]
  PIN sstream_i[153]
    DIRECTION INPUT ;
    USE SIGNAL ;
    ANTENNAGATEAREA 0.196500 ;
    PORT
      LAYER met2 ;
        RECT 346.470 0.000 346.750 4.000 ;
    END
  END sstream_i[153]
  PIN sstream_i[154]
    DIRECTION INPUT ;
    USE SIGNAL ;
    ANTENNAGATEAREA 0.196500 ;
    PORT
      LAYER met2 ;
        RECT 348.310 0.000 348.590 4.000 ;
    END
  END sstream_i[154]
  PIN sstream_i[155]
    DIRECTION INPUT ;
    USE SIGNAL ;
    ANTENNAGATEAREA 0.126000 ;
    PORT
      LAYER met2 ;
        RECT 350.150 0.000 350.430 4.000 ;
    END
  END sstream_i[155]
  PIN sstream_i[156]
    DIRECTION INPUT ;
    USE SIGNAL ;
    ANTENNAGATEAREA 0.126000 ;
    PORT
      LAYER met2 ;
        RECT 351.990 0.000 352.270 4.000 ;
    END
  END sstream_i[156]
  PIN sstream_i[157]
    DIRECTION INPUT ;
    USE SIGNAL ;
    ANTENNAGATEAREA 0.213000 ;
    PORT
      LAYER met2 ;
        RECT 353.830 0.000 354.110 4.000 ;
    END
  END sstream_i[157]
  PIN sstream_i[158]
    DIRECTION INPUT ;
    USE SIGNAL ;
    ANTENNAGATEAREA 0.213000 ;
    PORT
      LAYER met2 ;
        RECT 355.670 0.000 355.950 4.000 ;
    END
  END sstream_i[158]
  PIN sstream_i[159]
    DIRECTION INPUT ;
    USE SIGNAL ;
    ANTENNAGATEAREA 0.196500 ;
    PORT
      LAYER met2 ;
        RECT 357.510 0.000 357.790 4.000 ;
    END
  END sstream_i[159]
  PIN sstream_i[15]
    DIRECTION INPUT ;
    USE SIGNAL ;
    ANTENNAGATEAREA 0.247500 ;
    PORT
      LAYER met2 ;
        RECT 92.550 0.000 92.830 4.000 ;
    END
  END sstream_i[15]
  PIN sstream_i[160]
    DIRECTION INPUT ;
    USE SIGNAL ;
    ANTENNAGATEAREA 0.196500 ;
    PORT
      LAYER met2 ;
        RECT 359.350 0.000 359.630 4.000 ;
    END
  END sstream_i[160]
  PIN sstream_i[161]
    DIRECTION INPUT ;
    USE SIGNAL ;
    ANTENNAGATEAREA 0.126000 ;
    PORT
      LAYER met2 ;
        RECT 361.190 0.000 361.470 4.000 ;
    END
  END sstream_i[161]
  PIN sstream_i[162]
    DIRECTION INPUT ;
    USE SIGNAL ;
    ANTENNAGATEAREA 0.196500 ;
    PORT
      LAYER met2 ;
        RECT 363.030 0.000 363.310 4.000 ;
    END
  END sstream_i[162]
  PIN sstream_i[163]
    DIRECTION INPUT ;
    USE SIGNAL ;
    ANTENNAGATEAREA 0.213000 ;
    PORT
      LAYER met2 ;
        RECT 364.870 0.000 365.150 4.000 ;
    END
  END sstream_i[163]
  PIN sstream_i[164]
    DIRECTION INPUT ;
    USE SIGNAL ;
    ANTENNAGATEAREA 0.213000 ;
    PORT
      LAYER met2 ;
        RECT 366.710 0.000 366.990 4.000 ;
    END
  END sstream_i[164]
  PIN sstream_i[165]
    DIRECTION INPUT ;
    USE SIGNAL ;
    ANTENNAGATEAREA 0.213000 ;
    PORT
      LAYER met2 ;
        RECT 368.550 0.000 368.830 4.000 ;
    END
  END sstream_i[165]
  PIN sstream_i[166]
    DIRECTION INPUT ;
    USE SIGNAL ;
    ANTENNAGATEAREA 0.159000 ;
    PORT
      LAYER met2 ;
        RECT 370.390 0.000 370.670 4.000 ;
    END
  END sstream_i[166]
  PIN sstream_i[167]
    DIRECTION INPUT ;
    USE SIGNAL ;
    ANTENNAGATEAREA 0.159000 ;
    PORT
      LAYER met2 ;
        RECT 372.230 0.000 372.510 4.000 ;
    END
  END sstream_i[167]
  PIN sstream_i[168]
    DIRECTION INPUT ;
    USE SIGNAL ;
    ANTENNAGATEAREA 0.213000 ;
    PORT
      LAYER met2 ;
        RECT 374.070 0.000 374.350 4.000 ;
    END
  END sstream_i[168]
  PIN sstream_i[169]
    DIRECTION INPUT ;
    USE SIGNAL ;
    ANTENNAGATEAREA 0.159000 ;
    PORT
      LAYER met2 ;
        RECT 375.910 0.000 376.190 4.000 ;
    END
  END sstream_i[169]
  PIN sstream_i[16]
    DIRECTION INPUT ;
    USE SIGNAL ;
    ANTENNAGATEAREA 0.247500 ;
    PORT
      LAYER met2 ;
        RECT 94.390 0.000 94.670 4.000 ;
    END
  END sstream_i[16]
  PIN sstream_i[170]
    DIRECTION INPUT ;
    USE SIGNAL ;
    ANTENNAGATEAREA 0.159000 ;
    ANTENNADIFFAREA 0.434700 ;
    PORT
      LAYER met2 ;
        RECT 377.750 0.000 378.030 4.000 ;
    END
  END sstream_i[170]
  PIN sstream_i[171]
    DIRECTION INPUT ;
    USE SIGNAL ;
    ANTENNAGATEAREA 0.213000 ;
    PORT
      LAYER met2 ;
        RECT 379.590 0.000 379.870 4.000 ;
    END
  END sstream_i[171]
  PIN sstream_i[172]
    DIRECTION INPUT ;
    USE SIGNAL ;
    ANTENNAGATEAREA 0.247500 ;
    PORT
      LAYER met2 ;
        RECT 381.430 0.000 381.710 4.000 ;
    END
  END sstream_i[172]
  PIN sstream_i[173]
    DIRECTION INPUT ;
    USE SIGNAL ;
    ANTENNAGATEAREA 0.247500 ;
    PORT
      LAYER met2 ;
        RECT 383.270 0.000 383.550 4.000 ;
    END
  END sstream_i[173]
  PIN sstream_i[174]
    DIRECTION INPUT ;
    USE SIGNAL ;
    ANTENNAGATEAREA 0.247500 ;
    PORT
      LAYER met2 ;
        RECT 385.110 0.000 385.390 4.000 ;
    END
  END sstream_i[174]
  PIN sstream_i[175]
    DIRECTION INPUT ;
    USE SIGNAL ;
    ANTENNAGATEAREA 0.213000 ;
    PORT
      LAYER met2 ;
        RECT 386.950 0.000 387.230 4.000 ;
    END
  END sstream_i[175]
  PIN sstream_i[176]
    DIRECTION INPUT ;
    USE SIGNAL ;
    ANTENNAGATEAREA 0.213000 ;
    PORT
      LAYER met2 ;
        RECT 388.790 0.000 389.070 4.000 ;
    END
  END sstream_i[176]
  PIN sstream_i[177]
    DIRECTION INPUT ;
    USE SIGNAL ;
    ANTENNAGATEAREA 0.247500 ;
    PORT
      LAYER met2 ;
        RECT 390.630 0.000 390.910 4.000 ;
    END
  END sstream_i[177]
  PIN sstream_i[178]
    DIRECTION INPUT ;
    USE SIGNAL ;
    ANTENNAGATEAREA 0.247500 ;
    PORT
      LAYER met2 ;
        RECT 392.470 0.000 392.750 4.000 ;
    END
  END sstream_i[178]
  PIN sstream_i[179]
    DIRECTION INPUT ;
    USE SIGNAL ;
    ANTENNAGATEAREA 0.247500 ;
    PORT
      LAYER met2 ;
        RECT 394.310 0.000 394.590 4.000 ;
    END
  END sstream_i[179]
  PIN sstream_i[17]
    DIRECTION INPUT ;
    USE SIGNAL ;
    ANTENNAGATEAREA 0.247500 ;
    PORT
      LAYER met2 ;
        RECT 96.230 0.000 96.510 4.000 ;
    END
  END sstream_i[17]
  PIN sstream_i[180]
    DIRECTION INPUT ;
    USE SIGNAL ;
    ANTENNAGATEAREA 0.159000 ;
    PORT
      LAYER met2 ;
        RECT 396.150 0.000 396.430 4.000 ;
    END
  END sstream_i[180]
  PIN sstream_i[181]
    DIRECTION INPUT ;
    USE SIGNAL ;
    ANTENNAGATEAREA 0.247500 ;
    PORT
      LAYER met2 ;
        RECT 397.990 0.000 398.270 4.000 ;
    END
  END sstream_i[181]
  PIN sstream_i[182]
    DIRECTION INPUT ;
    USE SIGNAL ;
    ANTENNAGATEAREA 0.213000 ;
    PORT
      LAYER met2 ;
        RECT 399.830 0.000 400.110 4.000 ;
    END
  END sstream_i[182]
  PIN sstream_i[183]
    DIRECTION INPUT ;
    USE SIGNAL ;
    ANTENNAGATEAREA 0.213000 ;
    PORT
      LAYER met2 ;
        RECT 401.670 0.000 401.950 4.000 ;
    END
  END sstream_i[183]
  PIN sstream_i[184]
    DIRECTION INPUT ;
    USE SIGNAL ;
    ANTENNAGATEAREA 0.213000 ;
    PORT
      LAYER met2 ;
        RECT 403.510 0.000 403.790 4.000 ;
    END
  END sstream_i[184]
  PIN sstream_i[185]
    DIRECTION INPUT ;
    USE SIGNAL ;
    ANTENNAGATEAREA 0.159000 ;
    PORT
      LAYER met2 ;
        RECT 405.350 0.000 405.630 4.000 ;
    END
  END sstream_i[185]
  PIN sstream_i[186]
    DIRECTION INPUT ;
    USE SIGNAL ;
    ANTENNAGATEAREA 0.196500 ;
    PORT
      LAYER met2 ;
        RECT 407.190 0.000 407.470 4.000 ;
    END
  END sstream_i[186]
  PIN sstream_i[187]
    DIRECTION INPUT ;
    USE SIGNAL ;
    ANTENNAGATEAREA 0.196500 ;
    PORT
      LAYER met2 ;
        RECT 409.030 0.000 409.310 4.000 ;
    END
  END sstream_i[187]
  PIN sstream_i[188]
    DIRECTION INPUT ;
    USE SIGNAL ;
    ANTENNAGATEAREA 0.196500 ;
    PORT
      LAYER met2 ;
        RECT 410.870 0.000 411.150 4.000 ;
    END
  END sstream_i[188]
  PIN sstream_i[189]
    DIRECTION INPUT ;
    USE SIGNAL ;
    ANTENNAGATEAREA 0.196500 ;
    PORT
      LAYER met2 ;
        RECT 412.710 0.000 412.990 4.000 ;
    END
  END sstream_i[189]
  PIN sstream_i[18]
    DIRECTION INPUT ;
    USE SIGNAL ;
    ANTENNAGATEAREA 0.213000 ;
    PORT
      LAYER met2 ;
        RECT 98.070 0.000 98.350 4.000 ;
    END
  END sstream_i[18]
  PIN sstream_i[190]
    DIRECTION INPUT ;
    USE SIGNAL ;
    ANTENNAGATEAREA 0.196500 ;
    PORT
      LAYER met2 ;
        RECT 414.550 0.000 414.830 4.000 ;
    END
  END sstream_i[190]
  PIN sstream_i[191]
    DIRECTION INPUT ;
    USE SIGNAL ;
    ANTENNAGATEAREA 0.196500 ;
    PORT
      LAYER met2 ;
        RECT 416.390 0.000 416.670 4.000 ;
    END
  END sstream_i[191]
  PIN sstream_i[192]
    DIRECTION INPUT ;
    USE SIGNAL ;
    ANTENNAGATEAREA 0.196500 ;
    PORT
      LAYER met2 ;
        RECT 418.230 0.000 418.510 4.000 ;
    END
  END sstream_i[192]
  PIN sstream_i[193]
    DIRECTION INPUT ;
    USE SIGNAL ;
    ANTENNAGATEAREA 0.213000 ;
    PORT
      LAYER met2 ;
        RECT 420.070 0.000 420.350 4.000 ;
    END
  END sstream_i[193]
  PIN sstream_i[194]
    DIRECTION INPUT ;
    USE SIGNAL ;
    ANTENNAGATEAREA 0.213000 ;
    PORT
      LAYER met2 ;
        RECT 421.910 0.000 422.190 4.000 ;
    END
  END sstream_i[194]
  PIN sstream_i[195]
    DIRECTION INPUT ;
    USE SIGNAL ;
    ANTENNAGATEAREA 0.196500 ;
    PORT
      LAYER met2 ;
        RECT 423.750 0.000 424.030 4.000 ;
    END
  END sstream_i[195]
  PIN sstream_i[196]
    DIRECTION INPUT ;
    USE SIGNAL ;
    ANTENNAGATEAREA 0.213000 ;
    PORT
      LAYER met2 ;
        RECT 425.590 0.000 425.870 4.000 ;
    END
  END sstream_i[196]
  PIN sstream_i[197]
    DIRECTION INPUT ;
    USE SIGNAL ;
    ANTENNAGATEAREA 0.159000 ;
    PORT
      LAYER met2 ;
        RECT 427.430 0.000 427.710 4.000 ;
    END
  END sstream_i[197]
  PIN sstream_i[198]
    DIRECTION INPUT ;
    USE SIGNAL ;
    ANTENNAGATEAREA 0.159000 ;
    PORT
      LAYER met2 ;
        RECT 429.270 0.000 429.550 4.000 ;
    END
  END sstream_i[198]
  PIN sstream_i[199]
    DIRECTION INPUT ;
    USE SIGNAL ;
    ANTENNAGATEAREA 0.159000 ;
    PORT
      LAYER met2 ;
        RECT 431.110 0.000 431.390 4.000 ;
    END
  END sstream_i[199]
  PIN sstream_i[19]
    DIRECTION INPUT ;
    USE SIGNAL ;
    ANTENNAGATEAREA 0.247500 ;
    PORT
      LAYER met2 ;
        RECT 99.910 0.000 100.190 4.000 ;
    END
  END sstream_i[19]
  PIN sstream_i[1]
    DIRECTION INPUT ;
    USE SIGNAL ;
    ANTENNAGATEAREA 0.196500 ;
    PORT
      LAYER met2 ;
        RECT 66.790 0.000 67.070 4.000 ;
    END
  END sstream_i[1]
  PIN sstream_i[200]
    DIRECTION INPUT ;
    USE SIGNAL ;
    ANTENNAGATEAREA 0.159000 ;
    PORT
      LAYER met2 ;
        RECT 432.950 0.000 433.230 4.000 ;
    END
  END sstream_i[200]
  PIN sstream_i[201]
    DIRECTION INPUT ;
    USE SIGNAL ;
    ANTENNAGATEAREA 0.159000 ;
    PORT
      LAYER met2 ;
        RECT 434.790 0.000 435.070 4.000 ;
    END
  END sstream_i[201]
  PIN sstream_i[202]
    DIRECTION INPUT ;
    USE SIGNAL ;
    ANTENNAGATEAREA 0.213000 ;
    PORT
      LAYER met2 ;
        RECT 436.630 0.000 436.910 4.000 ;
    END
  END sstream_i[202]
  PIN sstream_i[203]
    DIRECTION INPUT ;
    USE SIGNAL ;
    ANTENNAGATEAREA 0.159000 ;
    PORT
      LAYER met2 ;
        RECT 438.470 0.000 438.750 4.000 ;
    END
  END sstream_i[203]
  PIN sstream_i[204]
    DIRECTION INPUT ;
    USE SIGNAL ;
    ANTENNAGATEAREA 0.247500 ;
    PORT
      LAYER met2 ;
        RECT 440.310 0.000 440.590 4.000 ;
    END
  END sstream_i[204]
  PIN sstream_i[205]
    DIRECTION INPUT ;
    USE SIGNAL ;
    ANTENNAGATEAREA 0.213000 ;
    PORT
      LAYER met2 ;
        RECT 442.150 0.000 442.430 4.000 ;
    END
  END sstream_i[205]
  PIN sstream_i[206]
    DIRECTION INPUT ;
    USE SIGNAL ;
    ANTENNAGATEAREA 0.247500 ;
    PORT
      LAYER met2 ;
        RECT 443.990 0.000 444.270 4.000 ;
    END
  END sstream_i[206]
  PIN sstream_i[207]
    DIRECTION INPUT ;
    USE SIGNAL ;
    ANTENNAGATEAREA 0.247500 ;
    PORT
      LAYER met2 ;
        RECT 445.830 0.000 446.110 4.000 ;
    END
  END sstream_i[207]
  PIN sstream_i[208]
    DIRECTION INPUT ;
    USE SIGNAL ;
    ANTENNAGATEAREA 0.247500 ;
    PORT
      LAYER met2 ;
        RECT 447.670 0.000 447.950 4.000 ;
    END
  END sstream_i[208]
  PIN sstream_i[209]
    DIRECTION INPUT ;
    USE SIGNAL ;
    ANTENNAGATEAREA 0.247500 ;
    PORT
      LAYER met2 ;
        RECT 449.510 0.000 449.790 4.000 ;
    END
  END sstream_i[209]
  PIN sstream_i[20]
    DIRECTION INPUT ;
    USE SIGNAL ;
    ANTENNAGATEAREA 0.247500 ;
    PORT
      LAYER met2 ;
        RECT 101.750 0.000 102.030 4.000 ;
    END
  END sstream_i[20]
  PIN sstream_i[210]
    DIRECTION INPUT ;
    USE SIGNAL ;
    ANTENNAGATEAREA 0.213000 ;
    PORT
      LAYER met2 ;
        RECT 451.350 0.000 451.630 4.000 ;
    END
  END sstream_i[210]
  PIN sstream_i[211]
    DIRECTION INPUT ;
    USE SIGNAL ;
    ANTENNAGATEAREA 0.247500 ;
    PORT
      LAYER met2 ;
        RECT 453.190 0.000 453.470 4.000 ;
    END
  END sstream_i[211]
  PIN sstream_i[212]
    DIRECTION INPUT ;
    USE SIGNAL ;
    ANTENNAGATEAREA 0.247500 ;
    PORT
      LAYER met2 ;
        RECT 455.030 0.000 455.310 4.000 ;
    END
  END sstream_i[212]
  PIN sstream_i[213]
    DIRECTION INPUT ;
    USE SIGNAL ;
    ANTENNAGATEAREA 0.213000 ;
    ANTENNADIFFAREA 0.434700 ;
    PORT
      LAYER met2 ;
        RECT 456.870 0.000 457.150 4.000 ;
    END
  END sstream_i[213]
  PIN sstream_i[214]
    DIRECTION INPUT ;
    USE SIGNAL ;
    ANTENNAGATEAREA 0.213000 ;
    PORT
      LAYER met2 ;
        RECT 458.710 0.000 458.990 4.000 ;
    END
  END sstream_i[214]
  PIN sstream_i[215]
    DIRECTION INPUT ;
    USE SIGNAL ;
    ANTENNAGATEAREA 0.159000 ;
    ANTENNADIFFAREA 0.434700 ;
    PORT
      LAYER met2 ;
        RECT 460.550 0.000 460.830 4.000 ;
    END
  END sstream_i[215]
  PIN sstream_i[216]
    DIRECTION INPUT ;
    USE SIGNAL ;
    ANTENNAGATEAREA 0.159000 ;
    PORT
      LAYER met2 ;
        RECT 462.390 0.000 462.670 4.000 ;
    END
  END sstream_i[216]
  PIN sstream_i[217]
    DIRECTION INPUT ;
    USE SIGNAL ;
    ANTENNAGATEAREA 0.213000 ;
    PORT
      LAYER met2 ;
        RECT 464.230 0.000 464.510 4.000 ;
    END
  END sstream_i[217]
  PIN sstream_i[218]
    DIRECTION INPUT ;
    USE SIGNAL ;
    ANTENNAGATEAREA 0.159000 ;
    PORT
      LAYER met2 ;
        RECT 466.070 0.000 466.350 4.000 ;
    END
  END sstream_i[218]
  PIN sstream_i[219]
    DIRECTION INPUT ;
    USE SIGNAL ;
    ANTENNAGATEAREA 0.213000 ;
    PORT
      LAYER met2 ;
        RECT 467.910 0.000 468.190 4.000 ;
    END
  END sstream_i[219]
  PIN sstream_i[21]
    DIRECTION INPUT ;
    USE SIGNAL ;
    ANTENNAGATEAREA 0.213000 ;
    PORT
      LAYER met2 ;
        RECT 103.590 0.000 103.870 4.000 ;
    END
  END sstream_i[21]
  PIN sstream_i[220]
    DIRECTION INPUT ;
    USE SIGNAL ;
    ANTENNAGATEAREA 0.213000 ;
    PORT
      LAYER met2 ;
        RECT 469.750 0.000 470.030 4.000 ;
    END
  END sstream_i[220]
  PIN sstream_i[221]
    DIRECTION INPUT ;
    USE SIGNAL ;
    ANTENNAGATEAREA 0.196500 ;
    PORT
      LAYER met2 ;
        RECT 471.590 0.000 471.870 4.000 ;
    END
  END sstream_i[221]
  PIN sstream_i[222]
    DIRECTION INPUT ;
    USE SIGNAL ;
    ANTENNAGATEAREA 0.196500 ;
    PORT
      LAYER met2 ;
        RECT 473.430 0.000 473.710 4.000 ;
    END
  END sstream_i[222]
  PIN sstream_i[223]
    DIRECTION INPUT ;
    USE SIGNAL ;
    ANTENNAGATEAREA 0.196500 ;
    PORT
      LAYER met2 ;
        RECT 475.270 0.000 475.550 4.000 ;
    END
  END sstream_i[223]
  PIN sstream_i[224]
    DIRECTION INPUT ;
    USE SIGNAL ;
    ANTENNAGATEAREA 0.213000 ;
    PORT
      LAYER met2 ;
        RECT 477.110 0.000 477.390 4.000 ;
    END
  END sstream_i[224]
  PIN sstream_i[225]
    DIRECTION INPUT ;
    USE SIGNAL ;
    ANTENNAGATEAREA 0.126000 ;
    PORT
      LAYER met2 ;
        RECT 478.950 0.000 479.230 4.000 ;
    END
  END sstream_i[225]
  PIN sstream_i[226]
    DIRECTION INPUT ;
    USE SIGNAL ;
    ANTENNAGATEAREA 0.126000 ;
    PORT
      LAYER met2 ;
        RECT 480.790 0.000 481.070 4.000 ;
    END
  END sstream_i[226]
  PIN sstream_i[227]
    DIRECTION INPUT ;
    USE SIGNAL ;
    ANTENNAGATEAREA 0.126000 ;
    PORT
      LAYER met2 ;
        RECT 482.630 0.000 482.910 4.000 ;
    END
  END sstream_i[227]
  PIN sstream_i[228]
    DIRECTION INPUT ;
    USE SIGNAL ;
    ANTENNAGATEAREA 0.213000 ;
    PORT
      LAYER met2 ;
        RECT 484.470 0.000 484.750 4.000 ;
    END
  END sstream_i[228]
  PIN sstream_i[229]
    DIRECTION INPUT ;
    USE SIGNAL ;
    ANTENNAGATEAREA 0.126000 ;
    PORT
      LAYER met2 ;
        RECT 486.310 0.000 486.590 4.000 ;
    END
  END sstream_i[229]
  PIN sstream_i[22]
    DIRECTION INPUT ;
    USE SIGNAL ;
    ANTENNAGATEAREA 0.247500 ;
    PORT
      LAYER met2 ;
        RECT 105.430 0.000 105.710 4.000 ;
    END
  END sstream_i[22]
  PIN sstream_i[230]
    DIRECTION INPUT ;
    USE SIGNAL ;
    ANTENNAGATEAREA 0.213000 ;
    PORT
      LAYER met2 ;
        RECT 488.150 0.000 488.430 4.000 ;
    END
  END sstream_i[230]
  PIN sstream_i[231]
    DIRECTION INPUT ;
    USE SIGNAL ;
    ANTENNAGATEAREA 0.247500 ;
    PORT
      LAYER met2 ;
        RECT 489.990 0.000 490.270 4.000 ;
    END
  END sstream_i[231]
  PIN sstream_i[232]
    DIRECTION INPUT ;
    USE SIGNAL ;
    ANTENNAGATEAREA 0.159000 ;
    PORT
      LAYER met2 ;
        RECT 491.830 0.000 492.110 4.000 ;
    END
  END sstream_i[232]
  PIN sstream_i[233]
    DIRECTION INPUT ;
    USE SIGNAL ;
    ANTENNAGATEAREA 0.159000 ;
    PORT
      LAYER met2 ;
        RECT 493.670 0.000 493.950 4.000 ;
    END
  END sstream_i[233]
  PIN sstream_i[234]
    DIRECTION INPUT ;
    USE SIGNAL ;
    ANTENNAGATEAREA 0.159000 ;
    PORT
      LAYER met2 ;
        RECT 495.510 0.000 495.790 4.000 ;
    END
  END sstream_i[234]
  PIN sstream_i[235]
    DIRECTION INPUT ;
    USE SIGNAL ;
    ANTENNAGATEAREA 0.213000 ;
    PORT
      LAYER met2 ;
        RECT 497.350 0.000 497.630 4.000 ;
    END
  END sstream_i[235]
  PIN sstream_i[236]
    DIRECTION INPUT ;
    USE SIGNAL ;
    ANTENNAGATEAREA 0.247500 ;
    PORT
      LAYER met2 ;
        RECT 499.190 0.000 499.470 4.000 ;
    END
  END sstream_i[236]
  PIN sstream_i[237]
    DIRECTION INPUT ;
    USE SIGNAL ;
    ANTENNAGATEAREA 0.247500 ;
    ANTENNADIFFAREA 0.434700 ;
    PORT
      LAYER met2 ;
        RECT 501.030 0.000 501.310 4.000 ;
    END
  END sstream_i[237]
  PIN sstream_i[238]
    DIRECTION INPUT ;
    USE SIGNAL ;
    ANTENNAGATEAREA 0.247500 ;
    PORT
      LAYER met2 ;
        RECT 502.870 0.000 503.150 4.000 ;
    END
  END sstream_i[238]
  PIN sstream_i[239]
    DIRECTION INPUT ;
    USE SIGNAL ;
    ANTENNAGATEAREA 0.213000 ;
    PORT
      LAYER met2 ;
        RECT 504.710 0.000 504.990 4.000 ;
    END
  END sstream_i[239]
  PIN sstream_i[23]
    DIRECTION INPUT ;
    USE SIGNAL ;
    ANTENNAGATEAREA 0.213000 ;
    PORT
      LAYER met2 ;
        RECT 107.270 0.000 107.550 4.000 ;
    END
  END sstream_i[23]
  PIN sstream_i[240]
    DIRECTION INPUT ;
    USE SIGNAL ;
    ANTENNAGATEAREA 0.213000 ;
    PORT
      LAYER met2 ;
        RECT 506.550 0.000 506.830 4.000 ;
    END
  END sstream_i[240]
  PIN sstream_i[241]
    DIRECTION INPUT ;
    USE SIGNAL ;
    ANTENNAGATEAREA 0.213000 ;
    ANTENNADIFFAREA 0.434700 ;
    PORT
      LAYER met2 ;
        RECT 508.390 0.000 508.670 4.000 ;
    END
  END sstream_i[241]
  PIN sstream_i[242]
    DIRECTION INPUT ;
    USE SIGNAL ;
    ANTENNAGATEAREA 0.247500 ;
    PORT
      LAYER met2 ;
        RECT 510.230 0.000 510.510 4.000 ;
    END
  END sstream_i[242]
  PIN sstream_i[243]
    DIRECTION INPUT ;
    USE SIGNAL ;
    ANTENNAGATEAREA 0.247500 ;
    PORT
      LAYER met2 ;
        RECT 512.070 0.000 512.350 4.000 ;
    END
  END sstream_i[243]
  PIN sstream_i[244]
    DIRECTION INPUT ;
    USE SIGNAL ;
    ANTENNAGATEAREA 0.159000 ;
    PORT
      LAYER met2 ;
        RECT 513.910 0.000 514.190 4.000 ;
    END
  END sstream_i[244]
  PIN sstream_i[245]
    DIRECTION INPUT ;
    USE SIGNAL ;
    ANTENNAGATEAREA 0.213000 ;
    PORT
      LAYER met2 ;
        RECT 515.750 0.000 516.030 4.000 ;
    END
  END sstream_i[245]
  PIN sstream_i[246]
    DIRECTION INPUT ;
    USE SIGNAL ;
    ANTENNAGATEAREA 0.213000 ;
    PORT
      LAYER met2 ;
        RECT 517.590 0.000 517.870 4.000 ;
    END
  END sstream_i[246]
  PIN sstream_i[247]
    DIRECTION INPUT ;
    USE SIGNAL ;
    ANTENNAGATEAREA 0.213000 ;
    PORT
      LAYER met2 ;
        RECT 519.430 0.000 519.710 4.000 ;
    END
  END sstream_i[247]
  PIN sstream_i[248]
    DIRECTION INPUT ;
    USE SIGNAL ;
    ANTENNAGATEAREA 0.213000 ;
    PORT
      LAYER met2 ;
        RECT 521.270 0.000 521.550 4.000 ;
    END
  END sstream_i[248]
  PIN sstream_i[249]
    DIRECTION INPUT ;
    USE SIGNAL ;
    ANTENNAGATEAREA 0.213000 ;
    PORT
      LAYER met2 ;
        RECT 523.110 0.000 523.390 4.000 ;
    END
  END sstream_i[249]
  PIN sstream_i[24]
    DIRECTION INPUT ;
    USE SIGNAL ;
    ANTENNAGATEAREA 0.213000 ;
    PORT
      LAYER met2 ;
        RECT 109.110 0.000 109.390 4.000 ;
    END
  END sstream_i[24]
  PIN sstream_i[250]
    DIRECTION INPUT ;
    USE SIGNAL ;
    ANTENNAGATEAREA 0.196500 ;
    PORT
      LAYER met2 ;
        RECT 524.950 0.000 525.230 4.000 ;
    END
  END sstream_i[250]
  PIN sstream_i[251]
    DIRECTION INPUT ;
    USE SIGNAL ;
    ANTENNAGATEAREA 0.126000 ;
    PORT
      LAYER met2 ;
        RECT 526.790 0.000 527.070 4.000 ;
    END
  END sstream_i[251]
  PIN sstream_i[252]
    DIRECTION INPUT ;
    USE SIGNAL ;
    ANTENNAGATEAREA 0.196500 ;
    PORT
      LAYER met2 ;
        RECT 528.630 0.000 528.910 4.000 ;
    END
  END sstream_i[252]
  PIN sstream_i[253]
    DIRECTION INPUT ;
    USE SIGNAL ;
    ANTENNAGATEAREA 0.196500 ;
    PORT
      LAYER met2 ;
        RECT 530.470 0.000 530.750 4.000 ;
    END
  END sstream_i[253]
  PIN sstream_i[254]
    DIRECTION INPUT ;
    USE SIGNAL ;
    ANTENNAGATEAREA 0.196500 ;
    PORT
      LAYER met2 ;
        RECT 532.310 0.000 532.590 4.000 ;
    END
  END sstream_i[254]
  PIN sstream_i[255]
    DIRECTION INPUT ;
    USE SIGNAL ;
    ANTENNAGATEAREA 0.196500 ;
    PORT
      LAYER met2 ;
        RECT 534.150 0.000 534.430 4.000 ;
    END
  END sstream_i[255]
  PIN sstream_i[256]
    DIRECTION INPUT ;
    USE SIGNAL ;
    ANTENNAGATEAREA 0.495000 ;
    PORT
      LAYER met2 ;
        RECT 535.990 0.000 536.270 4.000 ;
    END
  END sstream_i[256]
  PIN sstream_i[257]
    DIRECTION INPUT ;
    USE SIGNAL ;
    PORT
      LAYER met2 ;
        RECT 537.830 0.000 538.110 4.000 ;
    END
  END sstream_i[257]
  PIN sstream_i[25]
    DIRECTION INPUT ;
    USE SIGNAL ;
    ANTENNAGATEAREA 0.213000 ;
    PORT
      LAYER met2 ;
        RECT 110.950 0.000 111.230 4.000 ;
    END
  END sstream_i[25]
  PIN sstream_i[26]
    DIRECTION INPUT ;
    USE SIGNAL ;
    ANTENNAGATEAREA 0.213000 ;
    PORT
      LAYER met2 ;
        RECT 112.790 0.000 113.070 4.000 ;
    END
  END sstream_i[26]
  PIN sstream_i[27]
    DIRECTION INPUT ;
    USE SIGNAL ;
    ANTENNAGATEAREA 0.126000 ;
    PORT
      LAYER met2 ;
        RECT 114.630 0.000 114.910 4.000 ;
    END
  END sstream_i[27]
  PIN sstream_i[28]
    DIRECTION INPUT ;
    USE SIGNAL ;
    ANTENNAGATEAREA 0.196500 ;
    PORT
      LAYER met2 ;
        RECT 116.470 0.000 116.750 4.000 ;
    END
  END sstream_i[28]
  PIN sstream_i[29]
    DIRECTION INPUT ;
    USE SIGNAL ;
    ANTENNAGATEAREA 0.159000 ;
    PORT
      LAYER met2 ;
        RECT 118.310 0.000 118.590 4.000 ;
    END
  END sstream_i[29]
  PIN sstream_i[2]
    DIRECTION INPUT ;
    USE SIGNAL ;
    ANTENNAGATEAREA 0.196500 ;
    PORT
      LAYER met2 ;
        RECT 68.630 0.000 68.910 4.000 ;
    END
  END sstream_i[2]
  PIN sstream_i[30]
    DIRECTION INPUT ;
    USE SIGNAL ;
    ANTENNAGATEAREA 0.196500 ;
    PORT
      LAYER met2 ;
        RECT 120.150 0.000 120.430 4.000 ;
    END
  END sstream_i[30]
  PIN sstream_i[31]
    DIRECTION INPUT ;
    USE SIGNAL ;
    ANTENNAGATEAREA 0.126000 ;
    PORT
      LAYER met2 ;
        RECT 121.990 0.000 122.270 4.000 ;
    END
  END sstream_i[31]
  PIN sstream_i[32]
    DIRECTION INPUT ;
    USE SIGNAL ;
    ANTENNAGATEAREA 0.126000 ;
    PORT
      LAYER met2 ;
        RECT 123.830 0.000 124.110 4.000 ;
    END
  END sstream_i[32]
  PIN sstream_i[33]
    DIRECTION INPUT ;
    USE SIGNAL ;
    ANTENNAGATEAREA 0.213000 ;
    PORT
      LAYER met2 ;
        RECT 125.670 0.000 125.950 4.000 ;
    END
  END sstream_i[33]
  PIN sstream_i[34]
    DIRECTION INPUT ;
    USE SIGNAL ;
    ANTENNAGATEAREA 0.213000 ;
    PORT
      LAYER met2 ;
        RECT 127.510 0.000 127.790 4.000 ;
    END
  END sstream_i[34]
  PIN sstream_i[35]
    DIRECTION INPUT ;
    USE SIGNAL ;
    ANTENNAGATEAREA 0.196500 ;
    PORT
      LAYER met2 ;
        RECT 129.350 0.000 129.630 4.000 ;
    END
  END sstream_i[35]
  PIN sstream_i[36]
    DIRECTION INPUT ;
    USE SIGNAL ;
    ANTENNAGATEAREA 0.159000 ;
    ANTENNADIFFAREA 0.434700 ;
    PORT
      LAYER met2 ;
        RECT 131.190 0.000 131.470 4.000 ;
    END
  END sstream_i[36]
  PIN sstream_i[37]
    DIRECTION INPUT ;
    USE SIGNAL ;
    ANTENNAGATEAREA 0.213000 ;
    PORT
      LAYER met2 ;
        RECT 133.030 0.000 133.310 4.000 ;
    END
  END sstream_i[37]
  PIN sstream_i[38]
    DIRECTION INPUT ;
    USE SIGNAL ;
    ANTENNAGATEAREA 0.159000 ;
    ANTENNADIFFAREA 0.434700 ;
    PORT
      LAYER met2 ;
        RECT 134.870 0.000 135.150 4.000 ;
    END
  END sstream_i[38]
  PIN sstream_i[39]
    DIRECTION INPUT ;
    USE SIGNAL ;
    ANTENNAGATEAREA 0.213000 ;
    PORT
      LAYER met2 ;
        RECT 136.710 0.000 136.990 4.000 ;
    END
  END sstream_i[39]
  PIN sstream_i[3]
    DIRECTION INPUT ;
    USE SIGNAL ;
    ANTENNAGATEAREA 0.213000 ;
    PORT
      LAYER met2 ;
        RECT 70.470 0.000 70.750 4.000 ;
    END
  END sstream_i[3]
  PIN sstream_i[40]
    DIRECTION INPUT ;
    USE SIGNAL ;
    ANTENNAGATEAREA 0.159000 ;
    PORT
      LAYER met2 ;
        RECT 138.550 0.000 138.830 4.000 ;
    END
  END sstream_i[40]
  PIN sstream_i[41]
    DIRECTION INPUT ;
    USE SIGNAL ;
    ANTENNAGATEAREA 0.159000 ;
    PORT
      LAYER met2 ;
        RECT 140.390 0.000 140.670 4.000 ;
    END
  END sstream_i[41]
  PIN sstream_i[42]
    DIRECTION INPUT ;
    USE SIGNAL ;
    ANTENNAGATEAREA 0.213000 ;
    PORT
      LAYER met2 ;
        RECT 142.230 0.000 142.510 4.000 ;
    END
  END sstream_i[42]
  PIN sstream_i[43]
    DIRECTION INPUT ;
    USE SIGNAL ;
    ANTENNAGATEAREA 0.213000 ;
    PORT
      LAYER met2 ;
        RECT 144.070 0.000 144.350 4.000 ;
    END
  END sstream_i[43]
  PIN sstream_i[44]
    DIRECTION INPUT ;
    USE SIGNAL ;
    ANTENNAGATEAREA 0.213000 ;
    PORT
      LAYER met2 ;
        RECT 145.910 0.000 146.190 4.000 ;
    END
  END sstream_i[44]
  PIN sstream_i[45]
    DIRECTION INPUT ;
    USE SIGNAL ;
    ANTENNAGATEAREA 0.247500 ;
    PORT
      LAYER met2 ;
        RECT 147.750 0.000 148.030 4.000 ;
    END
  END sstream_i[45]
  PIN sstream_i[46]
    DIRECTION INPUT ;
    USE SIGNAL ;
    ANTENNAGATEAREA 0.247500 ;
    PORT
      LAYER met2 ;
        RECT 149.590 0.000 149.870 4.000 ;
    END
  END sstream_i[46]
  PIN sstream_i[47]
    DIRECTION INPUT ;
    USE SIGNAL ;
    ANTENNAGATEAREA 0.247500 ;
    PORT
      LAYER met2 ;
        RECT 151.430 0.000 151.710 4.000 ;
    END
  END sstream_i[47]
  PIN sstream_i[48]
    DIRECTION INPUT ;
    USE SIGNAL ;
    ANTENNAGATEAREA 0.247500 ;
    PORT
      LAYER met2 ;
        RECT 153.270 0.000 153.550 4.000 ;
    END
  END sstream_i[48]
  PIN sstream_i[49]
    DIRECTION INPUT ;
    USE SIGNAL ;
    ANTENNAGATEAREA 0.247500 ;
    PORT
      LAYER met2 ;
        RECT 155.110 0.000 155.390 4.000 ;
    END
  END sstream_i[49]
  PIN sstream_i[4]
    DIRECTION INPUT ;
    USE SIGNAL ;
    ANTENNAGATEAREA 0.213000 ;
    PORT
      LAYER met2 ;
        RECT 72.310 0.000 72.590 4.000 ;
    END
  END sstream_i[4]
  PIN sstream_i[50]
    DIRECTION INPUT ;
    USE SIGNAL ;
    ANTENNAGATEAREA 0.247500 ;
    PORT
      LAYER met2 ;
        RECT 156.950 0.000 157.230 4.000 ;
    END
  END sstream_i[50]
  PIN sstream_i[51]
    DIRECTION INPUT ;
    USE SIGNAL ;
    ANTENNAGATEAREA 0.247500 ;
    PORT
      LAYER met2 ;
        RECT 158.790 0.000 159.070 4.000 ;
    END
  END sstream_i[51]
  PIN sstream_i[52]
    DIRECTION INPUT ;
    USE SIGNAL ;
    ANTENNAGATEAREA 0.247500 ;
    PORT
      LAYER met2 ;
        RECT 160.630 0.000 160.910 4.000 ;
    END
  END sstream_i[52]
  PIN sstream_i[53]
    DIRECTION INPUT ;
    USE SIGNAL ;
    ANTENNAGATEAREA 0.247500 ;
    PORT
      LAYER met2 ;
        RECT 162.470 0.000 162.750 4.000 ;
    END
  END sstream_i[53]
  PIN sstream_i[54]
    DIRECTION INPUT ;
    USE SIGNAL ;
    ANTENNAGATEAREA 0.159000 ;
    PORT
      LAYER met2 ;
        RECT 164.310 0.000 164.590 4.000 ;
    END
  END sstream_i[54]
  PIN sstream_i[55]
    DIRECTION INPUT ;
    USE SIGNAL ;
    ANTENNAGATEAREA 0.213000 ;
    PORT
      LAYER met2 ;
        RECT 166.150 0.000 166.430 4.000 ;
    END
  END sstream_i[55]
  PIN sstream_i[56]
    DIRECTION INPUT ;
    USE SIGNAL ;
    ANTENNAGATEAREA 0.213000 ;
    PORT
      LAYER met2 ;
        RECT 167.990 0.000 168.270 4.000 ;
    END
  END sstream_i[56]
  PIN sstream_i[57]
    DIRECTION INPUT ;
    USE SIGNAL ;
    ANTENNAGATEAREA 0.213000 ;
    PORT
      LAYER met2 ;
        RECT 169.830 0.000 170.110 4.000 ;
    END
  END sstream_i[57]
  PIN sstream_i[58]
    DIRECTION INPUT ;
    USE SIGNAL ;
    ANTENNAGATEAREA 0.213000 ;
    PORT
      LAYER met2 ;
        RECT 171.670 0.000 171.950 4.000 ;
    END
  END sstream_i[58]
  PIN sstream_i[59]
    DIRECTION INPUT ;
    USE SIGNAL ;
    ANTENNAGATEAREA 0.213000 ;
    PORT
      LAYER met2 ;
        RECT 173.510 0.000 173.790 4.000 ;
    END
  END sstream_i[59]
  PIN sstream_i[5]
    DIRECTION INPUT ;
    USE SIGNAL ;
    ANTENNAGATEAREA 0.213000 ;
    PORT
      LAYER met2 ;
        RECT 74.150 0.000 74.430 4.000 ;
    END
  END sstream_i[5]
  PIN sstream_i[60]
    DIRECTION INPUT ;
    USE SIGNAL ;
    ANTENNAGATEAREA 0.196500 ;
    PORT
      LAYER met2 ;
        RECT 175.350 0.000 175.630 4.000 ;
    END
  END sstream_i[60]
  PIN sstream_i[61]
    DIRECTION INPUT ;
    USE SIGNAL ;
    ANTENNAGATEAREA 0.213000 ;
    PORT
      LAYER met2 ;
        RECT 177.190 0.000 177.470 4.000 ;
    END
  END sstream_i[61]
  PIN sstream_i[62]
    DIRECTION INPUT ;
    USE SIGNAL ;
    ANTENNAGATEAREA 0.196500 ;
    PORT
      LAYER met2 ;
        RECT 179.030 0.000 179.310 4.000 ;
    END
  END sstream_i[62]
  PIN sstream_i[63]
    DIRECTION INPUT ;
    USE SIGNAL ;
    ANTENNAGATEAREA 0.126000 ;
    PORT
      LAYER met2 ;
        RECT 180.870 0.000 181.150 4.000 ;
    END
  END sstream_i[63]
  PIN sstream_i[64]
    DIRECTION INPUT ;
    USE SIGNAL ;
    ANTENNAGATEAREA 0.126000 ;
    PORT
      LAYER met2 ;
        RECT 182.710 0.000 182.990 4.000 ;
    END
  END sstream_i[64]
  PIN sstream_i[65]
    DIRECTION INPUT ;
    USE SIGNAL ;
    ANTENNAGATEAREA 0.213000 ;
    PORT
      LAYER met2 ;
        RECT 184.550 0.000 184.830 4.000 ;
    END
  END sstream_i[65]
  PIN sstream_i[66]
    DIRECTION INPUT ;
    USE SIGNAL ;
    ANTENNAGATEAREA 0.213000 ;
    PORT
      LAYER met2 ;
        RECT 186.390 0.000 186.670 4.000 ;
    END
  END sstream_i[66]
  PIN sstream_i[67]
    DIRECTION INPUT ;
    USE SIGNAL ;
    ANTENNAGATEAREA 0.126000 ;
    PORT
      LAYER met2 ;
        RECT 188.230 0.000 188.510 4.000 ;
    END
  END sstream_i[67]
  PIN sstream_i[68]
    DIRECTION INPUT ;
    USE SIGNAL ;
    ANTENNAGATEAREA 0.126000 ;
    PORT
      LAYER met2 ;
        RECT 190.070 0.000 190.350 4.000 ;
    END
  END sstream_i[68]
  PIN sstream_i[69]
    DIRECTION INPUT ;
    USE SIGNAL ;
    ANTENNAGATEAREA 0.213000 ;
    PORT
      LAYER met2 ;
        RECT 191.910 0.000 192.190 4.000 ;
    END
  END sstream_i[69]
  PIN sstream_i[6]
    DIRECTION INPUT ;
    USE SIGNAL ;
    ANTENNAGATEAREA 0.213000 ;
    PORT
      LAYER met2 ;
        RECT 75.990 0.000 76.270 4.000 ;
    END
  END sstream_i[6]
  PIN sstream_i[70]
    DIRECTION INPUT ;
    USE SIGNAL ;
    ANTENNAGATEAREA 0.213000 ;
    PORT
      LAYER met2 ;
        RECT 193.750 0.000 194.030 4.000 ;
    END
  END sstream_i[70]
  PIN sstream_i[71]
    DIRECTION INPUT ;
    USE SIGNAL ;
    ANTENNAGATEAREA 0.247500 ;
    PORT
      LAYER met2 ;
        RECT 195.590 0.000 195.870 4.000 ;
    END
  END sstream_i[71]
  PIN sstream_i[72]
    DIRECTION INPUT ;
    USE SIGNAL ;
    ANTENNAGATEAREA 0.159000 ;
    PORT
      LAYER met2 ;
        RECT 197.430 0.000 197.710 4.000 ;
    END
  END sstream_i[72]
  PIN sstream_i[73]
    DIRECTION INPUT ;
    USE SIGNAL ;
    ANTENNAGATEAREA 0.159000 ;
    PORT
      LAYER met2 ;
        RECT 199.270 0.000 199.550 4.000 ;
    END
  END sstream_i[73]
  PIN sstream_i[74]
    DIRECTION INPUT ;
    USE SIGNAL ;
    ANTENNAGATEAREA 0.213000 ;
    PORT
      LAYER met2 ;
        RECT 201.110 0.000 201.390 4.000 ;
    END
  END sstream_i[74]
  PIN sstream_i[75]
    DIRECTION INPUT ;
    USE SIGNAL ;
    ANTENNAGATEAREA 0.159000 ;
    PORT
      LAYER met2 ;
        RECT 202.950 0.000 203.230 4.000 ;
    END
  END sstream_i[75]
  PIN sstream_i[76]
    DIRECTION INPUT ;
    USE SIGNAL ;
    ANTENNAGATEAREA 0.213000 ;
    PORT
      LAYER met2 ;
        RECT 204.790 0.000 205.070 4.000 ;
    END
  END sstream_i[76]
  PIN sstream_i[77]
    DIRECTION INPUT ;
    USE SIGNAL ;
    ANTENNAGATEAREA 0.213000 ;
    PORT
      LAYER met2 ;
        RECT 206.630 0.000 206.910 4.000 ;
    END
  END sstream_i[77]
  PIN sstream_i[78]
    DIRECTION INPUT ;
    USE SIGNAL ;
    ANTENNAGATEAREA 0.126000 ;
    PORT
      LAYER met2 ;
        RECT 208.470 0.000 208.750 4.000 ;
    END
  END sstream_i[78]
  PIN sstream_i[79]
    DIRECTION INPUT ;
    USE SIGNAL ;
    ANTENNAGATEAREA 0.196500 ;
    PORT
      LAYER met2 ;
        RECT 210.310 0.000 210.590 4.000 ;
    END
  END sstream_i[79]
  PIN sstream_i[7]
    DIRECTION INPUT ;
    USE SIGNAL ;
    ANTENNAGATEAREA 0.159000 ;
    PORT
      LAYER met2 ;
        RECT 77.830 0.000 78.110 4.000 ;
    END
  END sstream_i[7]
  PIN sstream_i[80]
    DIRECTION INPUT ;
    USE SIGNAL ;
    ANTENNAGATEAREA 0.213000 ;
    PORT
      LAYER met2 ;
        RECT 212.150 0.000 212.430 4.000 ;
    END
  END sstream_i[80]
  PIN sstream_i[81]
    DIRECTION INPUT ;
    USE SIGNAL ;
    ANTENNAGATEAREA 0.213000 ;
    PORT
      LAYER met2 ;
        RECT 213.990 0.000 214.270 4.000 ;
    END
  END sstream_i[81]
  PIN sstream_i[82]
    DIRECTION INPUT ;
    USE SIGNAL ;
    ANTENNAGATEAREA 0.159000 ;
    PORT
      LAYER met2 ;
        RECT 215.830 0.000 216.110 4.000 ;
    END
  END sstream_i[82]
  PIN sstream_i[83]
    DIRECTION INPUT ;
    USE SIGNAL ;
    ANTENNAGATEAREA 0.159000 ;
    PORT
      LAYER met2 ;
        RECT 217.670 0.000 217.950 4.000 ;
    END
  END sstream_i[83]
  PIN sstream_i[84]
    DIRECTION INPUT ;
    USE SIGNAL ;
    ANTENNAGATEAREA 0.247500 ;
    PORT
      LAYER met2 ;
        RECT 219.510 0.000 219.790 4.000 ;
    END
  END sstream_i[84]
  PIN sstream_i[85]
    DIRECTION INPUT ;
    USE SIGNAL ;
    ANTENNAGATEAREA 0.213000 ;
    PORT
      LAYER met2 ;
        RECT 221.350 0.000 221.630 4.000 ;
    END
  END sstream_i[85]
  PIN sstream_i[86]
    DIRECTION INPUT ;
    USE SIGNAL ;
    ANTENNAGATEAREA 0.196500 ;
    PORT
      LAYER met2 ;
        RECT 223.190 0.000 223.470 4.000 ;
    END
  END sstream_i[86]
  PIN sstream_i[87]
    DIRECTION INPUT ;
    USE SIGNAL ;
    ANTENNAGATEAREA 0.196500 ;
    PORT
      LAYER met2 ;
        RECT 225.030 0.000 225.310 4.000 ;
    END
  END sstream_i[87]
  PIN sstream_i[88]
    DIRECTION INPUT ;
    USE SIGNAL ;
    ANTENNAGATEAREA 0.213000 ;
    PORT
      LAYER met2 ;
        RECT 226.870 0.000 227.150 4.000 ;
    END
  END sstream_i[88]
  PIN sstream_i[89]
    DIRECTION INPUT ;
    USE SIGNAL ;
    ANTENNAGATEAREA 0.196500 ;
    PORT
      LAYER met2 ;
        RECT 228.710 0.000 228.990 4.000 ;
    END
  END sstream_i[89]
  PIN sstream_i[8]
    DIRECTION INPUT ;
    USE SIGNAL ;
    ANTENNAGATEAREA 0.213000 ;
    PORT
      LAYER met2 ;
        RECT 79.670 0.000 79.950 4.000 ;
    END
  END sstream_i[8]
  PIN sstream_i[90]
    DIRECTION INPUT ;
    USE SIGNAL ;
    ANTENNAGATEAREA 0.213000 ;
    PORT
      LAYER met2 ;
        RECT 230.550 0.000 230.830 4.000 ;
    END
  END sstream_i[90]
  PIN sstream_i[91]
    DIRECTION INPUT ;
    USE SIGNAL ;
    ANTENNAGATEAREA 0.213000 ;
    PORT
      LAYER met2 ;
        RECT 232.390 0.000 232.670 4.000 ;
    END
  END sstream_i[91]
  PIN sstream_i[92]
    DIRECTION INPUT ;
    USE SIGNAL ;
    ANTENNAGATEAREA 0.126000 ;
    PORT
      LAYER met2 ;
        RECT 234.230 0.000 234.510 4.000 ;
    END
  END sstream_i[92]
  PIN sstream_i[93]
    DIRECTION INPUT ;
    USE SIGNAL ;
    ANTENNAGATEAREA 0.126000 ;
    PORT
      LAYER met2 ;
        RECT 236.070 0.000 236.350 4.000 ;
    END
  END sstream_i[93]
  PIN sstream_i[94]
    DIRECTION INPUT ;
    USE SIGNAL ;
    ANTENNAGATEAREA 0.196500 ;
    PORT
      LAYER met2 ;
        RECT 237.910 0.000 238.190 4.000 ;
    END
  END sstream_i[94]
  PIN sstream_i[95]
    DIRECTION INPUT ;
    USE SIGNAL ;
    ANTENNAGATEAREA 0.196500 ;
    PORT
      LAYER met2 ;
        RECT 239.750 0.000 240.030 4.000 ;
    END
  END sstream_i[95]
  PIN sstream_i[96]
    DIRECTION INPUT ;
    USE SIGNAL ;
    ANTENNAGATEAREA 0.213000 ;
    PORT
      LAYER met2 ;
        RECT 241.590 0.000 241.870 4.000 ;
    END
  END sstream_i[96]
  PIN sstream_i[97]
    DIRECTION INPUT ;
    USE SIGNAL ;
    ANTENNAGATEAREA 0.126000 ;
    PORT
      LAYER met2 ;
        RECT 243.430 0.000 243.710 4.000 ;
    END
  END sstream_i[97]
  PIN sstream_i[98]
    DIRECTION INPUT ;
    USE SIGNAL ;
    ANTENNAGATEAREA 0.126000 ;
    PORT
      LAYER met2 ;
        RECT 245.270 0.000 245.550 4.000 ;
    END
  END sstream_i[98]
  PIN sstream_i[99]
    DIRECTION INPUT ;
    USE SIGNAL ;
    ANTENNAGATEAREA 0.126000 ;
    PORT
      LAYER met2 ;
        RECT 247.110 0.000 247.390 4.000 ;
    END
  END sstream_i[99]
  PIN sstream_i[9]
    DIRECTION INPUT ;
    USE SIGNAL ;
    ANTENNAGATEAREA 0.159000 ;
    PORT
      LAYER met2 ;
        RECT 81.510 0.000 81.790 4.000 ;
    END
  END sstream_i[9]
  PIN sstream_o
    DIRECTION OUTPUT TRISTATE ;
    USE SIGNAL ;
    ANTENNADIFFAREA 0.795200 ;
    PORT
      LAYER met2 ;
        RECT 539.670 0.000 539.950 4.000 ;
    END
  END sstream_o
  PIN vccd1
    DIRECTION INOUT ;
    USE POWER ;
    PORT
      LAYER met4 ;
        RECT 21.040 10.640 22.640 587.760 ;
    END
    PORT
      LAYER met4 ;
        RECT 174.640 10.640 176.240 587.760 ;
    END
    PORT
      LAYER met4 ;
        RECT 328.240 10.640 329.840 587.760 ;
    END
    PORT
      LAYER met4 ;
        RECT 481.840 10.640 483.440 587.760 ;
    END
  END vccd1
  PIN vssd1
    DIRECTION INOUT ;
    USE GROUND ;
    PORT
      LAYER met4 ;
        RECT 97.840 10.640 99.440 587.760 ;
    END
    PORT
      LAYER met4 ;
        RECT 251.440 10.640 253.040 587.760 ;
    END
    PORT
      LAYER met4 ;
        RECT 405.040 10.640 406.640 587.760 ;
    END
    PORT
      LAYER met4 ;
        RECT 558.640 10.640 560.240 587.760 ;
    END
  END vssd1
  OBS
      LAYER li1 ;
        RECT 5.520 10.795 594.320 587.605 ;
      LAYER met1 ;
        RECT 4.670 4.460 598.390 591.220 ;
      LAYER met2 ;
        RECT 4.690 595.720 20.510 596.770 ;
        RECT 21.350 595.720 26.030 596.770 ;
        RECT 26.870 595.720 31.550 596.770 ;
        RECT 32.390 595.720 37.070 596.770 ;
        RECT 37.910 595.720 42.590 596.770 ;
        RECT 43.430 595.720 48.110 596.770 ;
        RECT 48.950 595.720 53.630 596.770 ;
        RECT 54.470 595.720 59.150 596.770 ;
        RECT 59.990 595.720 64.670 596.770 ;
        RECT 65.510 595.720 70.190 596.770 ;
        RECT 71.030 595.720 75.710 596.770 ;
        RECT 76.550 595.720 81.230 596.770 ;
        RECT 82.070 595.720 86.750 596.770 ;
        RECT 87.590 595.720 92.270 596.770 ;
        RECT 93.110 595.720 97.790 596.770 ;
        RECT 98.630 595.720 103.310 596.770 ;
        RECT 104.150 595.720 108.830 596.770 ;
        RECT 109.670 595.720 114.350 596.770 ;
        RECT 115.190 595.720 119.870 596.770 ;
        RECT 120.710 595.720 125.390 596.770 ;
        RECT 126.230 595.720 130.910 596.770 ;
        RECT 131.750 595.720 136.430 596.770 ;
        RECT 137.270 595.720 141.950 596.770 ;
        RECT 142.790 595.720 147.470 596.770 ;
        RECT 148.310 595.720 152.990 596.770 ;
        RECT 153.830 595.720 158.510 596.770 ;
        RECT 159.350 595.720 164.030 596.770 ;
        RECT 164.870 595.720 169.550 596.770 ;
        RECT 170.390 595.720 175.070 596.770 ;
        RECT 175.910 595.720 180.590 596.770 ;
        RECT 181.430 595.720 186.110 596.770 ;
        RECT 186.950 595.720 191.630 596.770 ;
        RECT 192.470 595.720 197.150 596.770 ;
        RECT 197.990 595.720 202.670 596.770 ;
        RECT 203.510 595.720 208.190 596.770 ;
        RECT 209.030 595.720 213.710 596.770 ;
        RECT 214.550 595.720 219.230 596.770 ;
        RECT 220.070 595.720 224.750 596.770 ;
        RECT 225.590 595.720 230.270 596.770 ;
        RECT 231.110 595.720 235.790 596.770 ;
        RECT 236.630 595.720 241.310 596.770 ;
        RECT 242.150 595.720 246.830 596.770 ;
        RECT 247.670 595.720 252.350 596.770 ;
        RECT 253.190 595.720 257.870 596.770 ;
        RECT 258.710 595.720 263.390 596.770 ;
        RECT 264.230 595.720 268.910 596.770 ;
        RECT 269.750 595.720 274.430 596.770 ;
        RECT 275.270 595.720 279.950 596.770 ;
        RECT 280.790 595.720 285.470 596.770 ;
        RECT 286.310 595.720 290.990 596.770 ;
        RECT 291.830 595.720 296.510 596.770 ;
        RECT 297.350 595.720 302.030 596.770 ;
        RECT 302.870 595.720 307.550 596.770 ;
        RECT 308.390 595.720 313.070 596.770 ;
        RECT 313.910 595.720 318.590 596.770 ;
        RECT 319.430 595.720 324.110 596.770 ;
        RECT 324.950 595.720 329.630 596.770 ;
        RECT 330.470 595.720 335.150 596.770 ;
        RECT 335.990 595.720 340.670 596.770 ;
        RECT 341.510 595.720 346.190 596.770 ;
        RECT 347.030 595.720 351.710 596.770 ;
        RECT 352.550 595.720 357.230 596.770 ;
        RECT 358.070 595.720 362.750 596.770 ;
        RECT 363.590 595.720 368.270 596.770 ;
        RECT 369.110 595.720 373.790 596.770 ;
        RECT 374.630 595.720 379.310 596.770 ;
        RECT 380.150 595.720 384.830 596.770 ;
        RECT 385.670 595.720 390.350 596.770 ;
        RECT 391.190 595.720 395.870 596.770 ;
        RECT 396.710 595.720 401.390 596.770 ;
        RECT 402.230 595.720 406.910 596.770 ;
        RECT 407.750 595.720 412.430 596.770 ;
        RECT 413.270 595.720 417.950 596.770 ;
        RECT 418.790 595.720 423.470 596.770 ;
        RECT 424.310 595.720 428.990 596.770 ;
        RECT 429.830 595.720 434.510 596.770 ;
        RECT 435.350 595.720 440.030 596.770 ;
        RECT 440.870 595.720 445.550 596.770 ;
        RECT 446.390 595.720 451.070 596.770 ;
        RECT 451.910 595.720 456.590 596.770 ;
        RECT 457.430 595.720 462.110 596.770 ;
        RECT 462.950 595.720 467.630 596.770 ;
        RECT 468.470 595.720 473.150 596.770 ;
        RECT 473.990 595.720 478.670 596.770 ;
        RECT 479.510 595.720 484.190 596.770 ;
        RECT 485.030 595.720 489.710 596.770 ;
        RECT 490.550 595.720 495.230 596.770 ;
        RECT 496.070 595.720 500.750 596.770 ;
        RECT 501.590 595.720 506.270 596.770 ;
        RECT 507.110 595.720 511.790 596.770 ;
        RECT 512.630 595.720 517.310 596.770 ;
        RECT 518.150 595.720 522.830 596.770 ;
        RECT 523.670 595.720 528.350 596.770 ;
        RECT 529.190 595.720 533.870 596.770 ;
        RECT 534.710 595.720 539.390 596.770 ;
        RECT 540.230 595.720 544.910 596.770 ;
        RECT 545.750 595.720 550.430 596.770 ;
        RECT 551.270 595.720 555.950 596.770 ;
        RECT 556.790 595.720 561.470 596.770 ;
        RECT 562.310 595.720 566.990 596.770 ;
        RECT 567.830 595.720 572.510 596.770 ;
        RECT 573.350 595.720 578.030 596.770 ;
        RECT 578.870 595.720 598.360 596.770 ;
        RECT 4.690 4.280 598.360 595.720 ;
        RECT 4.690 3.555 59.150 4.280 ;
        RECT 59.990 3.555 60.990 4.280 ;
        RECT 61.830 3.555 62.830 4.280 ;
        RECT 63.670 3.555 64.670 4.280 ;
        RECT 65.510 3.555 66.510 4.280 ;
        RECT 67.350 3.555 68.350 4.280 ;
        RECT 69.190 3.555 70.190 4.280 ;
        RECT 71.030 3.555 72.030 4.280 ;
        RECT 72.870 3.555 73.870 4.280 ;
        RECT 74.710 3.555 75.710 4.280 ;
        RECT 76.550 3.555 77.550 4.280 ;
        RECT 78.390 3.555 79.390 4.280 ;
        RECT 80.230 3.555 81.230 4.280 ;
        RECT 82.070 3.555 83.070 4.280 ;
        RECT 83.910 3.555 84.910 4.280 ;
        RECT 85.750 3.555 86.750 4.280 ;
        RECT 87.590 3.555 88.590 4.280 ;
        RECT 89.430 3.555 90.430 4.280 ;
        RECT 91.270 3.555 92.270 4.280 ;
        RECT 93.110 3.555 94.110 4.280 ;
        RECT 94.950 3.555 95.950 4.280 ;
        RECT 96.790 3.555 97.790 4.280 ;
        RECT 98.630 3.555 99.630 4.280 ;
        RECT 100.470 3.555 101.470 4.280 ;
        RECT 102.310 3.555 103.310 4.280 ;
        RECT 104.150 3.555 105.150 4.280 ;
        RECT 105.990 3.555 106.990 4.280 ;
        RECT 107.830 3.555 108.830 4.280 ;
        RECT 109.670 3.555 110.670 4.280 ;
        RECT 111.510 3.555 112.510 4.280 ;
        RECT 113.350 3.555 114.350 4.280 ;
        RECT 115.190 3.555 116.190 4.280 ;
        RECT 117.030 3.555 118.030 4.280 ;
        RECT 118.870 3.555 119.870 4.280 ;
        RECT 120.710 3.555 121.710 4.280 ;
        RECT 122.550 3.555 123.550 4.280 ;
        RECT 124.390 3.555 125.390 4.280 ;
        RECT 126.230 3.555 127.230 4.280 ;
        RECT 128.070 3.555 129.070 4.280 ;
        RECT 129.910 3.555 130.910 4.280 ;
        RECT 131.750 3.555 132.750 4.280 ;
        RECT 133.590 3.555 134.590 4.280 ;
        RECT 135.430 3.555 136.430 4.280 ;
        RECT 137.270 3.555 138.270 4.280 ;
        RECT 139.110 3.555 140.110 4.280 ;
        RECT 140.950 3.555 141.950 4.280 ;
        RECT 142.790 3.555 143.790 4.280 ;
        RECT 144.630 3.555 145.630 4.280 ;
        RECT 146.470 3.555 147.470 4.280 ;
        RECT 148.310 3.555 149.310 4.280 ;
        RECT 150.150 3.555 151.150 4.280 ;
        RECT 151.990 3.555 152.990 4.280 ;
        RECT 153.830 3.555 154.830 4.280 ;
        RECT 155.670 3.555 156.670 4.280 ;
        RECT 157.510 3.555 158.510 4.280 ;
        RECT 159.350 3.555 160.350 4.280 ;
        RECT 161.190 3.555 162.190 4.280 ;
        RECT 163.030 3.555 164.030 4.280 ;
        RECT 164.870 3.555 165.870 4.280 ;
        RECT 166.710 3.555 167.710 4.280 ;
        RECT 168.550 3.555 169.550 4.280 ;
        RECT 170.390 3.555 171.390 4.280 ;
        RECT 172.230 3.555 173.230 4.280 ;
        RECT 174.070 3.555 175.070 4.280 ;
        RECT 175.910 3.555 176.910 4.280 ;
        RECT 177.750 3.555 178.750 4.280 ;
        RECT 179.590 3.555 180.590 4.280 ;
        RECT 181.430 3.555 182.430 4.280 ;
        RECT 183.270 3.555 184.270 4.280 ;
        RECT 185.110 3.555 186.110 4.280 ;
        RECT 186.950 3.555 187.950 4.280 ;
        RECT 188.790 3.555 189.790 4.280 ;
        RECT 190.630 3.555 191.630 4.280 ;
        RECT 192.470 3.555 193.470 4.280 ;
        RECT 194.310 3.555 195.310 4.280 ;
        RECT 196.150 3.555 197.150 4.280 ;
        RECT 197.990 3.555 198.990 4.280 ;
        RECT 199.830 3.555 200.830 4.280 ;
        RECT 201.670 3.555 202.670 4.280 ;
        RECT 203.510 3.555 204.510 4.280 ;
        RECT 205.350 3.555 206.350 4.280 ;
        RECT 207.190 3.555 208.190 4.280 ;
        RECT 209.030 3.555 210.030 4.280 ;
        RECT 210.870 3.555 211.870 4.280 ;
        RECT 212.710 3.555 213.710 4.280 ;
        RECT 214.550 3.555 215.550 4.280 ;
        RECT 216.390 3.555 217.390 4.280 ;
        RECT 218.230 3.555 219.230 4.280 ;
        RECT 220.070 3.555 221.070 4.280 ;
        RECT 221.910 3.555 222.910 4.280 ;
        RECT 223.750 3.555 224.750 4.280 ;
        RECT 225.590 3.555 226.590 4.280 ;
        RECT 227.430 3.555 228.430 4.280 ;
        RECT 229.270 3.555 230.270 4.280 ;
        RECT 231.110 3.555 232.110 4.280 ;
        RECT 232.950 3.555 233.950 4.280 ;
        RECT 234.790 3.555 235.790 4.280 ;
        RECT 236.630 3.555 237.630 4.280 ;
        RECT 238.470 3.555 239.470 4.280 ;
        RECT 240.310 3.555 241.310 4.280 ;
        RECT 242.150 3.555 243.150 4.280 ;
        RECT 243.990 3.555 244.990 4.280 ;
        RECT 245.830 3.555 246.830 4.280 ;
        RECT 247.670 3.555 248.670 4.280 ;
        RECT 249.510 3.555 250.510 4.280 ;
        RECT 251.350 3.555 252.350 4.280 ;
        RECT 253.190 3.555 254.190 4.280 ;
        RECT 255.030 3.555 256.030 4.280 ;
        RECT 256.870 3.555 257.870 4.280 ;
        RECT 258.710 3.555 259.710 4.280 ;
        RECT 260.550 3.555 261.550 4.280 ;
        RECT 262.390 3.555 263.390 4.280 ;
        RECT 264.230 3.555 265.230 4.280 ;
        RECT 266.070 3.555 267.070 4.280 ;
        RECT 267.910 3.555 268.910 4.280 ;
        RECT 269.750 3.555 270.750 4.280 ;
        RECT 271.590 3.555 272.590 4.280 ;
        RECT 273.430 3.555 274.430 4.280 ;
        RECT 275.270 3.555 276.270 4.280 ;
        RECT 277.110 3.555 278.110 4.280 ;
        RECT 278.950 3.555 279.950 4.280 ;
        RECT 280.790 3.555 281.790 4.280 ;
        RECT 282.630 3.555 283.630 4.280 ;
        RECT 284.470 3.555 285.470 4.280 ;
        RECT 286.310 3.555 287.310 4.280 ;
        RECT 288.150 3.555 289.150 4.280 ;
        RECT 289.990 3.555 290.990 4.280 ;
        RECT 291.830 3.555 292.830 4.280 ;
        RECT 293.670 3.555 294.670 4.280 ;
        RECT 295.510 3.555 296.510 4.280 ;
        RECT 297.350 3.555 298.350 4.280 ;
        RECT 299.190 3.555 300.190 4.280 ;
        RECT 301.030 3.555 302.030 4.280 ;
        RECT 302.870 3.555 303.870 4.280 ;
        RECT 304.710 3.555 305.710 4.280 ;
        RECT 306.550 3.555 307.550 4.280 ;
        RECT 308.390 3.555 309.390 4.280 ;
        RECT 310.230 3.555 311.230 4.280 ;
        RECT 312.070 3.555 313.070 4.280 ;
        RECT 313.910 3.555 314.910 4.280 ;
        RECT 315.750 3.555 316.750 4.280 ;
        RECT 317.590 3.555 318.590 4.280 ;
        RECT 319.430 3.555 320.430 4.280 ;
        RECT 321.270 3.555 322.270 4.280 ;
        RECT 323.110 3.555 324.110 4.280 ;
        RECT 324.950 3.555 325.950 4.280 ;
        RECT 326.790 3.555 327.790 4.280 ;
        RECT 328.630 3.555 329.630 4.280 ;
        RECT 330.470 3.555 331.470 4.280 ;
        RECT 332.310 3.555 333.310 4.280 ;
        RECT 334.150 3.555 335.150 4.280 ;
        RECT 335.990 3.555 336.990 4.280 ;
        RECT 337.830 3.555 338.830 4.280 ;
        RECT 339.670 3.555 340.670 4.280 ;
        RECT 341.510 3.555 342.510 4.280 ;
        RECT 343.350 3.555 344.350 4.280 ;
        RECT 345.190 3.555 346.190 4.280 ;
        RECT 347.030 3.555 348.030 4.280 ;
        RECT 348.870 3.555 349.870 4.280 ;
        RECT 350.710 3.555 351.710 4.280 ;
        RECT 352.550 3.555 353.550 4.280 ;
        RECT 354.390 3.555 355.390 4.280 ;
        RECT 356.230 3.555 357.230 4.280 ;
        RECT 358.070 3.555 359.070 4.280 ;
        RECT 359.910 3.555 360.910 4.280 ;
        RECT 361.750 3.555 362.750 4.280 ;
        RECT 363.590 3.555 364.590 4.280 ;
        RECT 365.430 3.555 366.430 4.280 ;
        RECT 367.270 3.555 368.270 4.280 ;
        RECT 369.110 3.555 370.110 4.280 ;
        RECT 370.950 3.555 371.950 4.280 ;
        RECT 372.790 3.555 373.790 4.280 ;
        RECT 374.630 3.555 375.630 4.280 ;
        RECT 376.470 3.555 377.470 4.280 ;
        RECT 378.310 3.555 379.310 4.280 ;
        RECT 380.150 3.555 381.150 4.280 ;
        RECT 381.990 3.555 382.990 4.280 ;
        RECT 383.830 3.555 384.830 4.280 ;
        RECT 385.670 3.555 386.670 4.280 ;
        RECT 387.510 3.555 388.510 4.280 ;
        RECT 389.350 3.555 390.350 4.280 ;
        RECT 391.190 3.555 392.190 4.280 ;
        RECT 393.030 3.555 394.030 4.280 ;
        RECT 394.870 3.555 395.870 4.280 ;
        RECT 396.710 3.555 397.710 4.280 ;
        RECT 398.550 3.555 399.550 4.280 ;
        RECT 400.390 3.555 401.390 4.280 ;
        RECT 402.230 3.555 403.230 4.280 ;
        RECT 404.070 3.555 405.070 4.280 ;
        RECT 405.910 3.555 406.910 4.280 ;
        RECT 407.750 3.555 408.750 4.280 ;
        RECT 409.590 3.555 410.590 4.280 ;
        RECT 411.430 3.555 412.430 4.280 ;
        RECT 413.270 3.555 414.270 4.280 ;
        RECT 415.110 3.555 416.110 4.280 ;
        RECT 416.950 3.555 417.950 4.280 ;
        RECT 418.790 3.555 419.790 4.280 ;
        RECT 420.630 3.555 421.630 4.280 ;
        RECT 422.470 3.555 423.470 4.280 ;
        RECT 424.310 3.555 425.310 4.280 ;
        RECT 426.150 3.555 427.150 4.280 ;
        RECT 427.990 3.555 428.990 4.280 ;
        RECT 429.830 3.555 430.830 4.280 ;
        RECT 431.670 3.555 432.670 4.280 ;
        RECT 433.510 3.555 434.510 4.280 ;
        RECT 435.350 3.555 436.350 4.280 ;
        RECT 437.190 3.555 438.190 4.280 ;
        RECT 439.030 3.555 440.030 4.280 ;
        RECT 440.870 3.555 441.870 4.280 ;
        RECT 442.710 3.555 443.710 4.280 ;
        RECT 444.550 3.555 445.550 4.280 ;
        RECT 446.390 3.555 447.390 4.280 ;
        RECT 448.230 3.555 449.230 4.280 ;
        RECT 450.070 3.555 451.070 4.280 ;
        RECT 451.910 3.555 452.910 4.280 ;
        RECT 453.750 3.555 454.750 4.280 ;
        RECT 455.590 3.555 456.590 4.280 ;
        RECT 457.430 3.555 458.430 4.280 ;
        RECT 459.270 3.555 460.270 4.280 ;
        RECT 461.110 3.555 462.110 4.280 ;
        RECT 462.950 3.555 463.950 4.280 ;
        RECT 464.790 3.555 465.790 4.280 ;
        RECT 466.630 3.555 467.630 4.280 ;
        RECT 468.470 3.555 469.470 4.280 ;
        RECT 470.310 3.555 471.310 4.280 ;
        RECT 472.150 3.555 473.150 4.280 ;
        RECT 473.990 3.555 474.990 4.280 ;
        RECT 475.830 3.555 476.830 4.280 ;
        RECT 477.670 3.555 478.670 4.280 ;
        RECT 479.510 3.555 480.510 4.280 ;
        RECT 481.350 3.555 482.350 4.280 ;
        RECT 483.190 3.555 484.190 4.280 ;
        RECT 485.030 3.555 486.030 4.280 ;
        RECT 486.870 3.555 487.870 4.280 ;
        RECT 488.710 3.555 489.710 4.280 ;
        RECT 490.550 3.555 491.550 4.280 ;
        RECT 492.390 3.555 493.390 4.280 ;
        RECT 494.230 3.555 495.230 4.280 ;
        RECT 496.070 3.555 497.070 4.280 ;
        RECT 497.910 3.555 498.910 4.280 ;
        RECT 499.750 3.555 500.750 4.280 ;
        RECT 501.590 3.555 502.590 4.280 ;
        RECT 503.430 3.555 504.430 4.280 ;
        RECT 505.270 3.555 506.270 4.280 ;
        RECT 507.110 3.555 508.110 4.280 ;
        RECT 508.950 3.555 509.950 4.280 ;
        RECT 510.790 3.555 511.790 4.280 ;
        RECT 512.630 3.555 513.630 4.280 ;
        RECT 514.470 3.555 515.470 4.280 ;
        RECT 516.310 3.555 517.310 4.280 ;
        RECT 518.150 3.555 519.150 4.280 ;
        RECT 519.990 3.555 520.990 4.280 ;
        RECT 521.830 3.555 522.830 4.280 ;
        RECT 523.670 3.555 524.670 4.280 ;
        RECT 525.510 3.555 526.510 4.280 ;
        RECT 527.350 3.555 528.350 4.280 ;
        RECT 529.190 3.555 530.190 4.280 ;
        RECT 531.030 3.555 532.030 4.280 ;
        RECT 532.870 3.555 533.870 4.280 ;
        RECT 534.710 3.555 535.710 4.280 ;
        RECT 536.550 3.555 537.550 4.280 ;
        RECT 538.390 3.555 539.390 4.280 ;
        RECT 540.230 3.555 598.360 4.280 ;
      LAYER met3 ;
        RECT 4.000 566.800 596.095 587.685 ;
        RECT 4.400 565.400 596.095 566.800 ;
        RECT 4.000 500.160 596.095 565.400 ;
        RECT 4.400 498.760 596.095 500.160 ;
        RECT 4.000 433.520 596.095 498.760 ;
        RECT 4.400 432.120 596.095 433.520 ;
        RECT 4.000 366.880 596.095 432.120 ;
        RECT 4.400 365.480 596.095 366.880 ;
        RECT 4.000 300.240 596.095 365.480 ;
        RECT 4.400 298.840 596.095 300.240 ;
        RECT 4.000 233.600 596.095 298.840 ;
        RECT 4.400 232.200 596.095 233.600 ;
        RECT 4.000 166.960 596.095 232.200 ;
        RECT 4.400 165.560 596.095 166.960 ;
        RECT 4.000 100.320 596.095 165.560 ;
        RECT 4.400 98.920 596.095 100.320 ;
        RECT 4.000 33.680 596.095 98.920 ;
        RECT 4.400 32.280 596.095 33.680 ;
        RECT 4.000 3.575 596.095 32.280 ;
      LAYER met4 ;
        RECT 7.655 10.240 20.640 584.625 ;
        RECT 23.040 10.240 97.440 584.625 ;
        RECT 99.840 10.240 174.240 584.625 ;
        RECT 176.640 10.240 251.040 584.625 ;
        RECT 253.440 10.240 327.840 584.625 ;
        RECT 330.240 10.240 404.640 584.625 ;
        RECT 407.040 10.240 481.440 584.625 ;
        RECT 483.840 10.240 558.240 584.625 ;
        RECT 560.640 10.240 588.505 584.625 ;
        RECT 7.655 3.575 588.505 10.240 ;
  END
END serializing_mailman_m
END LIBRARY

